###############################################################
#  Generated by:      Cadence Innovus 20.13-s083_1
#  OS:                Linux x86_64(Host ID iron-502-28)
#  Generated on:      Tue May 24 09:04:44 2022
#  Design:            top
#  Command:           write_lef_abstract -specifyTopLayer 6 -PGPinLayers {5 6} -noCutObs -stripePin results/top.lef
###############################################################

VERSION 5.8 ;

BUSBITCHARS "[]" ;
DIVIDERCHAR "/" ;

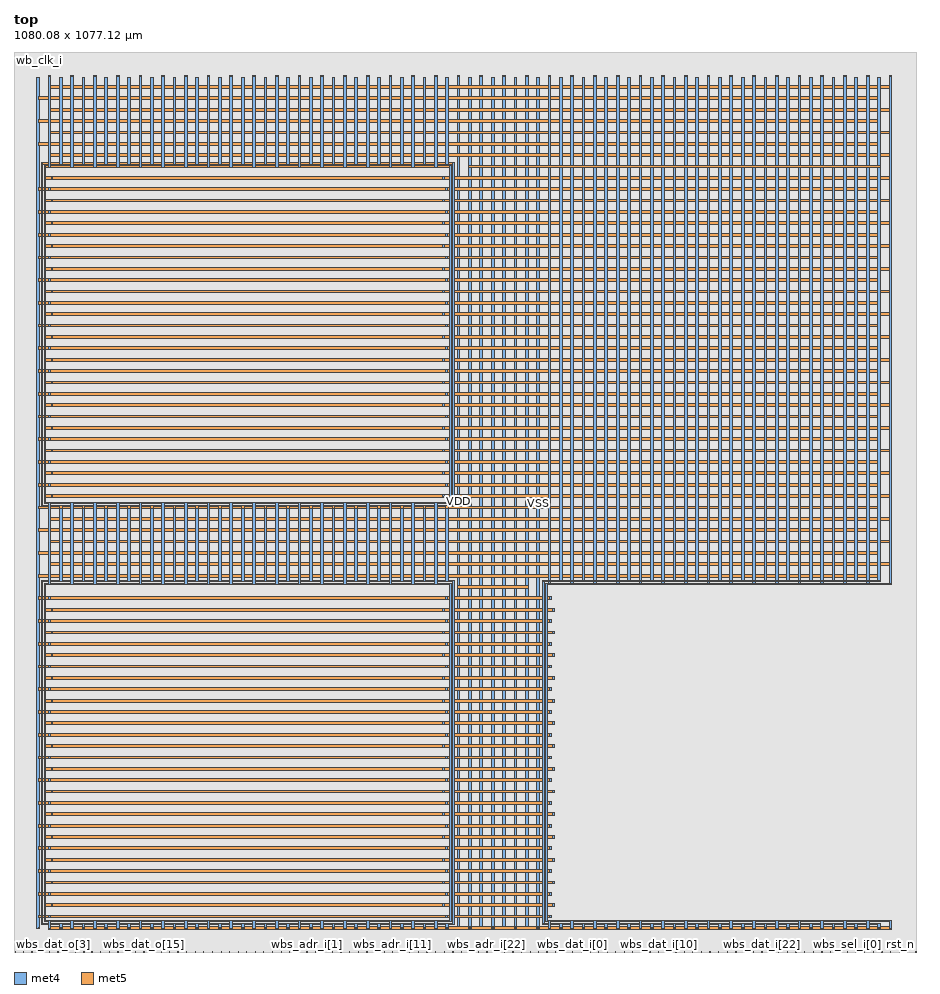
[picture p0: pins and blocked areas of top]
MACRO top
  CLASS BLOCK ;
  SIZE 1080.080000 BY 1077.120000 ;
  FOREIGN top 0.000000 0.000000 ;
  ORIGIN 0 0 ;
  SYMMETRY X Y R90 ;
  PIN clk
    DIRECTION INPUT ;
    USE SIGNAL ;
    ANTENNAPARTIALMETALAREA 0.4614 LAYER met4  ;
    ANTENNAPARTIALMETALSIDEAREA 2.456 LAYER met4  ;
    ANTENNAMODEL OXIDE1 ;
    ANTENNAGATEAREA 1.152 LAYER met4  ;
    ANTENNAMAXAREACAR 9.15953 LAYER met4  ;
    ANTENNAMAXSIDEAREACAR 47.4913 LAYER met4  ;
    ANTENNAMAXCUTCAR 0.114063 LAYER via4  ;
    PORT
      LAYER met4 ;
        RECT 0.000000 0.520000 0.800000 0.820000 ;
    END
  END clk
  PIN rst_n
    DIRECTION INPUT ;
    USE SIGNAL ;
    ANTENNAPARTIALMETALAREA 18.2562 LAYER met4  ;
    ANTENNAPARTIALMETALSIDEAREA 97.832 LAYER met4  ;
    ANTENNAMODEL OXIDE1 ;
    ANTENNAGATEAREA 4.6015 LAYER met4  ;
    ANTENNAMAXAREACAR 77.0933 LAYER met4  ;
    ANTENNAMAXSIDEAREACAR 375.091 LAYER met4  ;
    ANTENNAMAXCUTCAR 0.69315 LAYER via4  ;
    PORT
      LAYER met4 ;
        RECT 1079.240000 0.000000 1079.540000 0.800000 ;
    END
  END rst_n
  PIN wb_clk_i
    DIRECTION INPUT ;
    USE SIGNAL ;
    ANTENNAPARTIALMETALAREA 22.4322 LAYER met4  ;
    ANTENNAPARTIALMETALSIDEAREA 120.104 LAYER met4  ;
    ANTENNAMODEL OXIDE1 ;
    ANTENNAGATEAREA 0.477 LAYER met4  ;
    ANTENNAMAXAREACAR 77.5688 LAYER met4  ;
    ANTENNAMAXSIDEAREACAR 404.384 LAYER met4  ;
    ANTENNAMAXCUTCAR 1.05178 LAYER via4  ;
    PORT
      LAYER met4 ;
        RECT 0.000000 1076.560000 0.800000 1076.860000 ;
    END
  END wb_clk_i
  PIN wb_rst_i
    DIRECTION INPUT ;
    USE SIGNAL ;
    ANTENNAPARTIALMETALAREA 4.4604 LAYER met4  ;
    ANTENNAPARTIALMETALSIDEAREA 23.784 LAYER met4  ;
    ANTENNAMODEL OXIDE1 ;
    ANTENNAGATEAREA 8.3265 LAYER met4  ;
    ANTENNAMAXAREACAR 21.9302 LAYER met4  ;
    ANTENNAMAXSIDEAREACAR 109.513 LAYER met4  ;
    ANTENNAMAXCUTCAR 0.317271 LAYER via4  ;
    PORT
      LAYER met4 ;
        RECT 1069.580000 0.000000 1069.880000 0.800000 ;
    END
  END wb_rst_i
  PIN wbs_stb_i
    DIRECTION INPUT ;
    USE SIGNAL ;
    ANTENNAPARTIALMETALAREA 8.8044 LAYER met4  ;
    ANTENNAPARTIALMETALSIDEAREA 46.952 LAYER met4  ;
    ANTENNAMODEL OXIDE1 ;
    ANTENNAGATEAREA 0.2475 LAYER met4  ;
    ANTENNAMAXAREACAR 52.3097 LAYER met4  ;
    ANTENNAMAXSIDEAREACAR 278.307 LAYER met4  ;
    ANTENNAMAXCUTCAR 0.530909 LAYER via4  ;
    PORT
      LAYER met4 ;
        RECT 1059.230000 0.000000 1059.530000 0.800000 ;
    END
  END wbs_stb_i
  PIN wbs_cyc_i
    DIRECTION INPUT ;
    USE SIGNAL ;
    ANTENNAPARTIALMETALAREA 7.7064 LAYER met4  ;
    ANTENNAPARTIALMETALSIDEAREA 41.096 LAYER met4  ;
    ANTENNAMODEL OXIDE1 ;
    ANTENNAGATEAREA 0.2475 LAYER met4  ;
    ANTENNAMAXAREACAR 35.9594 LAYER met4  ;
    ANTENNAMAXSIDEAREACAR 190.17 LAYER met4  ;
    ANTENNAMAXCUTCAR 0.530909 LAYER via4  ;
    PORT
      LAYER met4 ;
        RECT 1048.880000 0.000000 1049.180000 0.800000 ;
    END
  END wbs_cyc_i
  PIN wbs_we_i
    DIRECTION INPUT ;
    USE SIGNAL ;
    ANTENNAPARTIALMETALAREA 0.855 LAYER met4  ;
    ANTENNAPARTIALMETALSIDEAREA 5.496 LAYER met4  ;
    ANTENNAMODEL OXIDE1 ;
    ANTENNAGATEAREA 0.126 LAYER met4  ;
    ANTENNAMAXAREACAR 59.1905 LAYER met4  ;
    ANTENNAMAXSIDEAREACAR 309.278 LAYER met4  ;
    ANTENNAMAXCUTCAR 1.04286 LAYER via4  ;
    PORT
      LAYER met4 ;
        RECT 1038.530000 0.000000 1038.830000 0.800000 ;
    END
  END wbs_we_i
  PIN wbs_sel_i[3]
    DIRECTION INPUT ;
    USE SIGNAL ;
    PORT
      LAYER met4 ;
        RECT 1028.180000 0.000000 1028.480000 0.800000 ;
    END
  END wbs_sel_i[3]
  PIN wbs_sel_i[2]
    DIRECTION INPUT ;
    USE SIGNAL ;
    PORT
      LAYER met4 ;
        RECT 1017.830000 0.000000 1018.130000 0.800000 ;
    END
  END wbs_sel_i[2]
  PIN wbs_sel_i[1]
    DIRECTION INPUT ;
    USE SIGNAL ;
    PORT
      LAYER met4 ;
        RECT 1007.480000 0.000000 1007.780000 0.800000 ;
    END
  END wbs_sel_i[1]
  PIN wbs_sel_i[0]
    DIRECTION INPUT ;
    USE SIGNAL ;
    PORT
      LAYER met4 ;
        RECT 997.130000 0.000000 997.430000 0.800000 ;
    END
  END wbs_sel_i[0]
  PIN wbs_dat_i[31]
    DIRECTION INPUT ;
    USE SIGNAL ;
    ANTENNAPARTIALMETALAREA 8.6214 LAYER met4  ;
    ANTENNAPARTIALMETALSIDEAREA 45.976 LAYER met4  ;
    ANTENNAMODEL OXIDE1 ;
    ANTENNAGATEAREA 0.126 LAYER met4  ;
    ANTENNAMAXAREACAR 73.4778 LAYER met4  ;
    ANTENNAMAXSIDEAREACAR 389.548 LAYER met4  ;
    ANTENNAMAXCUTCAR 1.04286 LAYER via4  ;
    PORT
      LAYER met4 ;
        RECT 987.470000 0.000000 987.770000 0.800000 ;
    END
  END wbs_dat_i[31]
  PIN wbs_dat_i[30]
    DIRECTION INPUT ;
    USE SIGNAL ;
    ANTENNAPARTIALMETALAREA 8.4384 LAYER met4  ;
    ANTENNAPARTIALMETALSIDEAREA 45 LAYER met4  ;
    ANTENNAMODEL OXIDE1 ;
    ANTENNAGATEAREA 0.126 LAYER met4  ;
    ANTENNAMAXAREACAR 79.5143 LAYER met4  ;
    ANTENNAMAXSIDEAREACAR 420.96 LAYER met4  ;
    ANTENNAMAXCUTCAR 1.04286 LAYER via4  ;
    PORT
      LAYER met4 ;
        RECT 977.120000 0.000000 977.420000 0.800000 ;
    END
  END wbs_dat_i[30]
  PIN wbs_dat_i[29]
    DIRECTION INPUT ;
    USE SIGNAL ;
    ANTENNAPARTIALMETALAREA 8.0724 LAYER met4  ;
    ANTENNAPARTIALMETALSIDEAREA 43.048 LAYER met4  ;
    ANTENNAMODEL OXIDE1 ;
    ANTENNAGATEAREA 0.126 LAYER met4  ;
    ANTENNAMAXAREACAR 72.7563 LAYER met4  ;
    ANTENNAMAXSIDEAREACAR 383.31 LAYER met4  ;
    ANTENNAMAXCUTCAR 1.04286 LAYER via4  ;
    PORT
      LAYER met4 ;
        RECT 966.770000 0.000000 967.070000 0.800000 ;
    END
  END wbs_dat_i[29]
  PIN wbs_dat_i[28]
    DIRECTION INPUT ;
    USE SIGNAL ;
    ANTENNAPARTIALMETALAREA 4.698 LAYER met4  ;
    ANTENNAPARTIALMETALSIDEAREA 25.992 LAYER met4  ;
    ANTENNAMODEL OXIDE1 ;
    ANTENNAGATEAREA 0.126 LAYER met4  ;
    ANTENNAMAXAREACAR 71.4944 LAYER met4  ;
    ANTENNAMAXSIDEAREACAR 376.802 LAYER met4  ;
    ANTENNAMAXCUTCAR 1.04286 LAYER via4  ;
    PORT
      LAYER met4 ;
        RECT 956.420000 0.000000 956.720000 0.800000 ;
    END
  END wbs_dat_i[28]
  PIN wbs_dat_i[27]
    DIRECTION INPUT ;
    USE SIGNAL ;
    ANTENNAPARTIALMETALAREA 8.6214 LAYER met4  ;
    ANTENNAPARTIALMETALSIDEAREA 45.976 LAYER met4  ;
    ANTENNAMODEL OXIDE1 ;
    ANTENNAGATEAREA 0.126 LAYER met4  ;
    ANTENNAMAXAREACAR 80.0071 LAYER met4  ;
    ANTENNAMAXSIDEAREACAR 421.659 LAYER met4  ;
    ANTENNAMAXCUTCAR 1.04286 LAYER via4  ;
    PORT
      LAYER met4 ;
        RECT 946.070000 0.000000 946.370000 0.800000 ;
    END
  END wbs_dat_i[27]
  PIN wbs_dat_i[26]
    DIRECTION INPUT ;
    USE SIGNAL ;
    ANTENNAPARTIALMETALAREA 7.1574 LAYER met4  ;
    ANTENNAPARTIALMETALSIDEAREA 38.168 LAYER met4  ;
    ANTENNAMODEL OXIDE1 ;
    ANTENNAGATEAREA 0.126 LAYER met4  ;
    ANTENNAMAXAREACAR 68.0734 LAYER met4  ;
    ANTENNAMAXSIDEAREACAR 354.278 LAYER met4  ;
    ANTENNAMAXCUTCAR 1.04286 LAYER via4  ;
    PORT
      LAYER met4 ;
        RECT 935.720000 0.000000 936.020000 0.800000 ;
    END
  END wbs_dat_i[26]
  PIN wbs_dat_i[25]
    DIRECTION INPUT ;
    USE SIGNAL ;
    ANTENNAPARTIALMETALAREA 8.0724 LAYER met4  ;
    ANTENNAPARTIALMETALSIDEAREA 43.048 LAYER met4  ;
    ANTENNAMODEL OXIDE1 ;
    ANTENNAGATEAREA 0.126 LAYER met4  ;
    ANTENNAMAXAREACAR 75.9881 LAYER met4  ;
    ANTENNAMAXSIDEAREACAR 400.183 LAYER met4  ;
    ANTENNAMAXCUTCAR 1.04286 LAYER via4  ;
    PORT
      LAYER met4 ;
        RECT 925.370000 0.000000 925.670000 0.800000 ;
    END
  END wbs_dat_i[25]
  PIN wbs_dat_i[24]
    DIRECTION INPUT ;
    USE SIGNAL ;
    ANTENNAPARTIALMETALAREA 8.6214 LAYER met4  ;
    ANTENNAPARTIALMETALSIDEAREA 45.976 LAYER met4  ;
    ANTENNAMODEL OXIDE1 ;
    ANTENNAGATEAREA 0.126 LAYER met4  ;
    ANTENNAMAXAREACAR 75.0246 LAYER met4  ;
    ANTENNAMAXSIDEAREACAR 397.278 LAYER met4  ;
    ANTENNAMAXCUTCAR 1.04286 LAYER via4  ;
    PORT
      LAYER met4 ;
        RECT 915.020000 0.000000 915.320000 0.800000 ;
    END
  END wbs_dat_i[24]
  PIN wbs_dat_i[23]
    DIRECTION INPUT ;
    USE SIGNAL ;
    ANTENNAPARTIALMETALAREA 8.175 LAYER met4  ;
    ANTENNAPARTIALMETALSIDEAREA 44.536 LAYER met4  ;
    ANTENNAMODEL OXIDE1 ;
    ANTENNAGATEAREA 0.126 LAYER met4  ;
    ANTENNAMAXAREACAR 91.3944 LAYER met4  ;
    ANTENNAMAXSIDEAREACAR 488.968 LAYER met4  ;
    ANTENNAMAXCUTCAR 1.04286 LAYER via4  ;
    PORT
      LAYER met4 ;
        RECT 904.670000 0.000000 904.970000 0.800000 ;
    END
  END wbs_dat_i[23]
  PIN wbs_dat_i[22]
    DIRECTION INPUT ;
    USE SIGNAL ;
    ANTENNAPARTIALMETALAREA 7.3984 LAYER met4  ;
    ANTENNAPARTIALMETALSIDEAREA 35.328 LAYER met4  ;
    ANTENNAPARTIALCUTAREA 0.64 LAYER via4  ;
    ANTENNAPARTIALMETALAREA 5.872 LAYER met5  ;
    ANTENNAPARTIALMETALSIDEAREA 12.648 LAYER met5  ;
    ANTENNAMODEL OXIDE1 ;
    ANTENNAGATEAREA 0.126 LAYER met5  ;
    ANTENNAMAXAREACAR 98.6127 LAYER met5  ;
    ANTENNAMAXSIDEAREACAR 346.69 LAYER met5  ;
    PORT
      LAYER met4 ;
        RECT 895.010000 0.000000 895.310000 0.800000 ;
    END
  END wbs_dat_i[22]
  PIN wbs_dat_i[21]
    DIRECTION INPUT ;
    USE SIGNAL ;
    ANTENNAPARTIALMETALAREA 7.3404 LAYER met4  ;
    ANTENNAPARTIALMETALSIDEAREA 39.144 LAYER met4  ;
    ANTENNAMODEL OXIDE1 ;
    ANTENNAGATEAREA 0.126 LAYER met4  ;
    ANTENNAMAXAREACAR 68.6032 LAYER met4  ;
    ANTENNAMAXSIDEAREACAR 360.77 LAYER met4  ;
    ANTENNAMAXCUTCAR 1.04286 LAYER via4  ;
    PORT
      LAYER met4 ;
        RECT 884.660000 0.000000 884.960000 0.800000 ;
    END
  END wbs_dat_i[21]
  PIN wbs_dat_i[20]
    DIRECTION INPUT ;
    USE SIGNAL ;
    ANTENNAPARTIALMETALAREA 8.6214 LAYER met4  ;
    ANTENNAPARTIALMETALSIDEAREA 45.976 LAYER met4  ;
    ANTENNAMODEL OXIDE1 ;
    ANTENNAGATEAREA 0.126 LAYER met4  ;
    ANTENNAMAXAREACAR 78.4738 LAYER met4  ;
    ANTENNAMAXSIDEAREACAR 413.992 LAYER met4  ;
    ANTENNAMAXCUTCAR 1.04286 LAYER via4  ;
    PORT
      LAYER met4 ;
        RECT 874.310000 0.000000 874.610000 0.800000 ;
    END
  END wbs_dat_i[20]
  PIN wbs_dat_i[19]
    DIRECTION INPUT ;
    USE SIGNAL ;
    ANTENNAPARTIALMETALAREA 5.2024 LAYER met4  ;
    ANTENNAPARTIALMETALSIDEAREA 23.616 LAYER met4  ;
    ANTENNAPARTIALCUTAREA 0.64 LAYER via4  ;
    ANTENNAPARTIALMETALAREA 19.184 LAYER met5  ;
    ANTENNAPARTIALMETALSIDEAREA 40.296 LAYER met5  ;
    ANTENNAMODEL OXIDE1 ;
    ANTENNAGATEAREA 0.126 LAYER met5  ;
    ANTENNAMAXAREACAR 190.813 LAYER met5  ;
    ANTENNAMAXSIDEAREACAR 491.349 LAYER met5  ;
    PORT
      LAYER met4 ;
        RECT 863.960000 0.000000 864.260000 0.800000 ;
    END
  END wbs_dat_i[19]
  PIN wbs_dat_i[18]
    DIRECTION INPUT ;
    USE SIGNAL ;
    ANTENNAPARTIALMETALAREA 8.6214 LAYER met4  ;
    ANTENNAPARTIALMETALSIDEAREA 45.976 LAYER met4  ;
    ANTENNAMODEL OXIDE1 ;
    ANTENNAGATEAREA 0.126 LAYER met4  ;
    ANTENNAMAXAREACAR 75.9183 LAYER met4  ;
    ANTENNAMAXSIDEAREACAR 401.214 LAYER met4  ;
    ANTENNAMAXCUTCAR 1.04286 LAYER via4  ;
    PORT
      LAYER met4 ;
        RECT 853.610000 0.000000 853.910000 0.800000 ;
    END
  END wbs_dat_i[18]
  PIN wbs_dat_i[17]
    DIRECTION INPUT ;
    USE SIGNAL ;
    ANTENNAPARTIALMETALAREA 0.2034 LAYER met4  ;
    ANTENNAPARTIALMETALSIDEAREA 1.08 LAYER met4  ;
    ANTENNAMODEL OXIDE1 ;
    ANTENNAGATEAREA 0.126 LAYER met4  ;
    ANTENNAMAXAREACAR 44.25 LAYER met4  ;
    ANTENNAMAXSIDEAREACAR 220.857 LAYER met4  ;
    ANTENNAMAXCUTCAR 1.04286 LAYER via4  ;
    PORT
      LAYER met4 ;
        RECT 843.260000 0.000000 843.560000 0.800000 ;
    END
  END wbs_dat_i[17]
  PIN wbs_dat_i[16]
    DIRECTION INPUT ;
    USE SIGNAL ;
    ANTENNAPARTIALMETALAREA 8.0724 LAYER met4  ;
    ANTENNAPARTIALMETALSIDEAREA 43.048 LAYER met4  ;
    ANTENNAMODEL OXIDE1 ;
    ANTENNAGATEAREA 0.126 LAYER met4  ;
    ANTENNAMAXAREACAR 78.3246 LAYER met4  ;
    ANTENNAMAXSIDEAREACAR 413.325 LAYER met4  ;
    ANTENNAMAXCUTCAR 1.04286 LAYER via4  ;
    PORT
      LAYER met4 ;
        RECT 832.910000 0.000000 833.210000 0.800000 ;
    END
  END wbs_dat_i[16]
  PIN wbs_dat_i[15]
    DIRECTION INPUT ;
    USE SIGNAL ;
    ANTENNAPARTIALMETALAREA 8.9874 LAYER met4  ;
    ANTENNAPARTIALMETALSIDEAREA 47.928 LAYER met4  ;
    ANTENNAMODEL OXIDE1 ;
    ANTENNAGATEAREA 0.126 LAYER met4  ;
    ANTENNAMAXAREACAR 83.4286 LAYER met4  ;
    ANTENNAMAXSIDEAREACAR 440.159 LAYER met4  ;
    ANTENNAMAXCUTCAR 1.04286 LAYER via4  ;
    PORT
      LAYER met4 ;
        RECT 822.560000 0.000000 822.860000 0.800000 ;
    END
  END wbs_dat_i[15]
  PIN wbs_dat_i[14]
    DIRECTION INPUT ;
    USE SIGNAL ;
    ANTENNAPARTIALMETALAREA 8.6214 LAYER met4  ;
    ANTENNAPARTIALMETALSIDEAREA 45.976 LAYER met4  ;
    ANTENNAMODEL OXIDE1 ;
    ANTENNAGATEAREA 0.126 LAYER met4  ;
    ANTENNAMAXAREACAR 79.7341 LAYER met4  ;
    ANTENNAMAXSIDEAREACAR 421.373 LAYER met4  ;
    ANTENNAMAXCUTCAR 1.04286 LAYER via4  ;
    PORT
      LAYER met4 ;
        RECT 812.210000 0.000000 812.510000 0.800000 ;
    END
  END wbs_dat_i[14]
  PIN wbs_dat_i[13]
    DIRECTION INPUT ;
    USE SIGNAL ;
    ANTENNAPARTIALMETALAREA 8.0724 LAYER met4  ;
    ANTENNAPARTIALMETALSIDEAREA 43.048 LAYER met4  ;
    ANTENNAMODEL OXIDE1 ;
    ANTENNAGATEAREA 0.126 LAYER met4  ;
    ANTENNAMAXAREACAR 76.3341 LAYER met4  ;
    ANTENNAMAXSIDEAREACAR 401.198 LAYER met4  ;
    ANTENNAMAXCUTCAR 1.04286 LAYER via4  ;
    PORT
      LAYER met4 ;
        RECT 802.550000 0.000000 802.850000 0.800000 ;
    END
  END wbs_dat_i[13]
  PIN wbs_dat_i[12]
    DIRECTION INPUT ;
    USE SIGNAL ;
    ANTENNAPARTIALMETALAREA 7.3404 LAYER met4  ;
    ANTENNAPARTIALMETALSIDEAREA 39.144 LAYER met4  ;
    ANTENNAMODEL OXIDE1 ;
    ANTENNAGATEAREA 0.126 LAYER met4  ;
    ANTENNAMAXAREACAR 68.7183 LAYER met4  ;
    ANTENNAMAXSIDEAREACAR 361.881 LAYER met4  ;
    ANTENNAMAXCUTCAR 1.04286 LAYER via4  ;
    PORT
      LAYER met4 ;
        RECT 792.200000 0.000000 792.500000 0.800000 ;
    END
  END wbs_dat_i[12]
  PIN wbs_dat_i[11]
    DIRECTION INPUT ;
    USE SIGNAL ;
    ANTENNAPARTIALMETALAREA 8.0724 LAYER met4  ;
    ANTENNAPARTIALMETALSIDEAREA 43.048 LAYER met4  ;
    ANTENNAMODEL OXIDE1 ;
    ANTENNAGATEAREA 0.126 LAYER met4  ;
    ANTENNAMAXAREACAR 72.8484 LAYER met4  ;
    ANTENNAMAXSIDEAREACAR 384.119 LAYER met4  ;
    ANTENNAMAXCUTCAR 1.04286 LAYER via4  ;
    PORT
      LAYER met4 ;
        RECT 781.850000 0.000000 782.150000 0.800000 ;
    END
  END wbs_dat_i[11]
  PIN wbs_dat_i[10]
    DIRECTION INPUT ;
    USE SIGNAL ;
    ANTENNAPARTIALMETALAREA 8.4384 LAYER met4  ;
    ANTENNAPARTIALMETALSIDEAREA 45 LAYER met4  ;
    ANTENNAMODEL OXIDE1 ;
    ANTENNAGATEAREA 0.126 LAYER met4  ;
    ANTENNAMAXAREACAR 76.6246 LAYER met4  ;
    ANTENNAMAXSIDEAREACAR 404.881 LAYER met4  ;
    ANTENNAMAXCUTCAR 1.04286 LAYER via4  ;
    PORT
      LAYER met4 ;
        RECT 771.500000 0.000000 771.800000 0.800000 ;
    END
  END wbs_dat_i[10]
  PIN wbs_dat_i[9]
    DIRECTION INPUT ;
    USE SIGNAL ;
    ANTENNAPARTIALMETALAREA 1.587 LAYER met4  ;
    ANTENNAPARTIALMETALSIDEAREA 9.4 LAYER met4  ;
    ANTENNAMODEL OXIDE1 ;
    ANTENNAGATEAREA 0.126 LAYER met4  ;
    ANTENNAMAXAREACAR 57.4849 LAYER met4  ;
    ANTENNAMAXSIDEAREACAR 299.984 LAYER met4  ;
    ANTENNAMAXCUTCAR 1.04286 LAYER via4  ;
    PORT
      LAYER met4 ;
        RECT 761.150000 0.000000 761.450000 0.800000 ;
    END
  END wbs_dat_i[9]
  PIN wbs_dat_i[8]
    DIRECTION INPUT ;
    USE SIGNAL ;
    ANTENNAPARTIALMETALAREA 2.709 LAYER met4  ;
    ANTENNAPARTIALMETALSIDEAREA 15.384 LAYER met4  ;
    ANTENNAMODEL OXIDE1 ;
    ANTENNAGATEAREA 0.126 LAYER met4  ;
    ANTENNAMAXAREACAR 66.1095 LAYER met4  ;
    ANTENNAMAXSIDEAREACAR 348.802 LAYER met4  ;
    ANTENNAMAXCUTCAR 1.04286 LAYER via4  ;
    PORT
      LAYER met4 ;
        RECT 750.800000 0.000000 751.100000 0.800000 ;
    END
  END wbs_dat_i[8]
  PIN wbs_dat_i[7]
    DIRECTION INPUT ;
    USE SIGNAL ;
    ANTENNAPARTIALMETALAREA 0.855 LAYER met4  ;
    ANTENNAPARTIALMETALSIDEAREA 5.496 LAYER met4  ;
    ANTENNAMODEL OXIDE1 ;
    ANTENNAGATEAREA 0.126 LAYER met4  ;
    ANTENNAMAXAREACAR 61.823 LAYER met4  ;
    ANTENNAMAXSIDEAREACAR 318.643 LAYER met4  ;
    ANTENNAMAXCUTCAR 1.04286 LAYER via4  ;
    PORT
      LAYER met4 ;
        RECT 740.450000 0.000000 740.750000 0.800000 ;
    END
  END wbs_dat_i[7]
  PIN wbs_dat_i[6]
    DIRECTION INPUT ;
    USE SIGNAL ;
    ANTENNAPARTIALMETALAREA 3.783 LAYER met4  ;
    ANTENNAPARTIALMETALSIDEAREA 21.112 LAYER met4  ;
    ANTENNAMODEL OXIDE1 ;
    ANTENNAGATEAREA 0.126 LAYER met4  ;
    ANTENNAMAXAREACAR 63.4754 LAYER met4  ;
    ANTENNAMAXSIDEAREACAR 333.556 LAYER met4  ;
    ANTENNAMAXCUTCAR 1.04286 LAYER via4  ;
    PORT
      LAYER met4 ;
        RECT 730.100000 0.000000 730.400000 0.800000 ;
    END
  END wbs_dat_i[6]
  PIN wbs_dat_i[5]
    DIRECTION INPUT ;
    USE SIGNAL ;
    ANTENNAPARTIALMETALAREA 1.953 LAYER met4  ;
    ANTENNAPARTIALMETALSIDEAREA 11.352 LAYER met4  ;
    ANTENNAMODEL OXIDE1 ;
    ANTENNAGATEAREA 0.126 LAYER met4  ;
    ANTENNAMAXAREACAR 63.5246 LAYER met4  ;
    ANTENNAMAXSIDEAREACAR 333.159 LAYER met4  ;
    ANTENNAMAXCUTCAR 1.04286 LAYER via4  ;
    PORT
      LAYER met4 ;
        RECT 719.750000 0.000000 720.050000 0.800000 ;
    END
  END wbs_dat_i[5]
  PIN wbs_dat_i[4]
    DIRECTION INPUT ;
    USE SIGNAL ;
    ANTENNAPARTIALMETALAREA 1.221 LAYER met4  ;
    ANTENNAPARTIALMETALSIDEAREA 7.448 LAYER met4  ;
    ANTENNAMODEL OXIDE1 ;
    ANTENNAGATEAREA 0.126 LAYER met4  ;
    ANTENNAMAXAREACAR 73.3357 LAYER met4  ;
    ANTENNAMAXSIDEAREACAR 380.825 LAYER met4  ;
    ANTENNAMAXCUTCAR 1.04286 LAYER via4  ;
    PORT
      LAYER met4 ;
        RECT 710.090000 0.000000 710.390000 0.800000 ;
    END
  END wbs_dat_i[4]
  PIN wbs_dat_i[3]
    DIRECTION INPUT ;
    USE SIGNAL ;
    ANTENNAPARTIALMETALAREA 4.332 LAYER met4  ;
    ANTENNAPARTIALMETALSIDEAREA 24.04 LAYER met4  ;
    ANTENNAMODEL OXIDE1 ;
    ANTENNAGATEAREA 0.126 LAYER met4  ;
    ANTENNAMAXAREACAR 64.546 LAYER met4  ;
    ANTENNAMAXSIDEAREACAR 342.722 LAYER met4  ;
    ANTENNAMAXCUTCAR 1.04286 LAYER via4  ;
    PORT
      LAYER met4 ;
        RECT 699.740000 0.000000 700.040000 0.800000 ;
    END
  END wbs_dat_i[3]
  PIN wbs_dat_i[2]
    DIRECTION INPUT ;
    USE SIGNAL ;
    ANTENNAPARTIALMETALAREA 3.234 LAYER met4  ;
    ANTENNAPARTIALMETALSIDEAREA 18.184 LAYER met4  ;
    ANTENNAMODEL OXIDE1 ;
    ANTENNAGATEAREA 0.126 LAYER met4  ;
    ANTENNAMAXAREACAR 63.5972 LAYER met4  ;
    ANTENNAMAXSIDEAREACAR 322.936 LAYER met4  ;
    ANTENNAMAXCUTCAR 1.04286 LAYER via4  ;
    PORT
      LAYER met4 ;
        RECT 689.390000 0.000000 689.690000 0.800000 ;
    END
  END wbs_dat_i[2]
  PIN wbs_dat_i[1]
    DIRECTION INPUT ;
    USE SIGNAL ;
    ANTENNAPARTIALMETALAREA 2.319 LAYER met4  ;
    ANTENNAPARTIALMETALSIDEAREA 13.304 LAYER met4  ;
    ANTENNAMODEL OXIDE1 ;
    ANTENNAGATEAREA 0.126 LAYER met4  ;
    ANTENNAMAXAREACAR 78.0643 LAYER met4  ;
    ANTENNAMAXSIDEAREACAR 406.071 LAYER met4  ;
    ANTENNAMAXCUTCAR 1.04286 LAYER via4  ;
    PORT
      LAYER met4 ;
        RECT 679.040000 0.000000 679.340000 0.800000 ;
    END
  END wbs_dat_i[1]
  PIN wbs_dat_i[0]
    DIRECTION INPUT ;
    USE SIGNAL ;
    ANTENNAPARTIALMETALAREA 2.685 LAYER met4  ;
    ANTENNAPARTIALMETALSIDEAREA 15.256 LAYER met4  ;
    ANTENNAMODEL OXIDE1 ;
    ANTENNAGATEAREA 0.126 LAYER met4  ;
    ANTENNAMAXAREACAR 106.781 LAYER met4  ;
    ANTENNAMAXSIDEAREACAR 543.976 LAYER met4  ;
    ANTENNAMAXCUTCAR 1.04286 LAYER via4  ;
    PORT
      LAYER met4 ;
        RECT 668.690000 0.000000 668.990000 0.800000 ;
    END
  END wbs_dat_i[0]
  PIN wbs_adr_i[31]
    DIRECTION INPUT ;
    USE SIGNAL ;
    ANTENNAPARTIALMETALAREA 1.587 LAYER met4  ;
    ANTENNAPARTIALMETALSIDEAREA 9.4 LAYER met4  ;
    ANTENNAMODEL OXIDE1 ;
    ANTENNAGATEAREA 0.126 LAYER met4  ;
    ANTENNAMAXAREACAR 70.9282 LAYER met4  ;
    ANTENNAMAXSIDEAREACAR 358.603 LAYER met4  ;
    ANTENNAMAXCUTCAR 1.04286 LAYER via4  ;
    PORT
      LAYER met4 ;
        RECT 658.340000 0.000000 658.640000 0.800000 ;
    END
  END wbs_adr_i[31]
  PIN wbs_adr_i[30]
    DIRECTION INPUT ;
    USE SIGNAL ;
    ANTENNAPARTIALMETALAREA 4.1424 LAYER met4  ;
    ANTENNAPARTIALMETALSIDEAREA 22.088 LAYER met4  ;
    ANTENNAMODEL OXIDE1 ;
    ANTENNAGATEAREA 0.126 LAYER met4  ;
    ANTENNAMAXAREACAR 129.885 LAYER met4  ;
    ANTENNAMAXSIDEAREACAR 668.77 LAYER met4  ;
    ANTENNAMAXCUTCAR 1.04286 LAYER via4  ;
    PORT
      LAYER met4 ;
        RECT 647.990000 0.000000 648.290000 0.800000 ;
    END
  END wbs_adr_i[30]
  PIN wbs_adr_i[29]
    DIRECTION INPUT ;
    USE SIGNAL ;
    ANTENNAPARTIALMETALAREA 9.2184 LAYER met4  ;
    ANTENNAPARTIALMETALSIDEAREA 49.16 LAYER met4  ;
    ANTENNAMODEL OXIDE1 ;
    ANTENNAGATEAREA 0.2475 LAYER met4  ;
    ANTENNAMAXAREACAR 90.6792 LAYER met4  ;
    ANTENNAMAXSIDEAREACAR 478.424 LAYER met4  ;
    ANTENNAMAXCUTCAR 0.530909 LAYER via4  ;
    PORT
      LAYER met4 ;
        RECT 637.640000 0.000000 637.940000 0.800000 ;
    END
  END wbs_adr_i[29]
  PIN wbs_adr_i[28]
    DIRECTION INPUT ;
    USE SIGNAL ;
    ANTENNAPARTIALMETALAREA 4.8264 LAYER met4  ;
    ANTENNAPARTIALMETALSIDEAREA 25.736 LAYER met4  ;
    ANTENNAMODEL OXIDE1 ;
    ANTENNAGATEAREA 0.2475 LAYER met4  ;
    ANTENNAMAXAREACAR 80.8723 LAYER met4  ;
    ANTENNAMAXSIDEAREACAR 423.79 LAYER met4  ;
    ANTENNAMAXCUTCAR 0.530909 LAYER via4  ;
    PORT
      LAYER met4 ;
        RECT 627.980000 0.000000 628.280000 0.800000 ;
    END
  END wbs_adr_i[28]
  PIN wbs_adr_i[27]
    DIRECTION INPUT ;
    USE SIGNAL ;
    ANTENNAPARTIALMETALAREA 6.0594 LAYER met4  ;
    ANTENNAPARTIALMETALSIDEAREA 32.312 LAYER met4  ;
    ANTENNAMODEL OXIDE1 ;
    ANTENNAGATEAREA 0.126 LAYER met4  ;
    ANTENNAMAXAREACAR 64.3516 LAYER met4  ;
    ANTENNAMAXSIDEAREACAR 334.087 LAYER met4  ;
    ANTENNAMAXCUTCAR 1.04286 LAYER via4  ;
    PORT
      LAYER met4 ;
        RECT 617.630000 0.000000 617.930000 0.800000 ;
    END
  END wbs_adr_i[27]
  PIN wbs_adr_i[26]
    DIRECTION INPUT ;
    USE SIGNAL ;
    ANTENNAPARTIALMETALAREA 8.4384 LAYER met4  ;
    ANTENNAPARTIALMETALSIDEAREA 45 LAYER met4  ;
    ANTENNAMODEL OXIDE1 ;
    ANTENNAGATEAREA 0.126 LAYER met4  ;
    ANTENNAMAXAREACAR 92.8361 LAYER met4  ;
    ANTENNAMAXSIDEAREACAR 490.96 LAYER met4  ;
    ANTENNAMAXCUTCAR 1.04286 LAYER via4  ;
    PORT
      LAYER met4 ;
        RECT 607.280000 0.000000 607.580000 0.800000 ;
    END
  END wbs_adr_i[26]
  PIN wbs_adr_i[25]
    DIRECTION INPUT ;
    USE SIGNAL ;
    ANTENNAPARTIALMETALAREA 8.2794 LAYER met4  ;
    ANTENNAPARTIALMETALSIDEAREA 44.152 LAYER met4  ;
    ANTENNAMODEL OXIDE1 ;
    ANTENNAGATEAREA 0.126 LAYER met4  ;
    ANTENNAMAXAREACAR 117.358 LAYER met4  ;
    ANTENNAMAXSIDEAREACAR 619.762 LAYER met4  ;
    ANTENNAMAXCUTCAR 1.04286 LAYER via4  ;
    PORT
      LAYER met4 ;
        RECT 596.930000 0.000000 597.230000 0.800000 ;
    END
  END wbs_adr_i[25]
  PIN wbs_adr_i[24]
    DIRECTION INPUT ;
    USE SIGNAL ;
    ANTENNAPARTIALMETALAREA 4.0464 LAYER met4  ;
    ANTENNAPARTIALMETALSIDEAREA 21.576 LAYER met4  ;
    ANTENNAMODEL OXIDE1 ;
    ANTENNAGATEAREA 0.126 LAYER met4  ;
    ANTENNAMAXAREACAR 76.1492 LAYER met4  ;
    ANTENNAMAXSIDEAREACAR 385.222 LAYER met4  ;
    ANTENNAMAXCUTCAR 1.04286 LAYER via4  ;
    PORT
      LAYER met4 ;
        RECT 586.580000 0.000000 586.880000 0.800000 ;
    END
  END wbs_adr_i[24]
  PIN wbs_adr_i[23]
    DIRECTION INPUT ;
    USE SIGNAL ;
    ANTENNAPARTIALMETALAREA 8.8044 LAYER met4  ;
    ANTENNAPARTIALMETALSIDEAREA 46.952 LAYER met4  ;
    ANTENNAMODEL OXIDE1 ;
    ANTENNAGATEAREA 0.126 LAYER met4  ;
    ANTENNAMAXAREACAR 80.3837 LAYER met4  ;
    ANTENNAMAXSIDEAREACAR 412.722 LAYER met4  ;
    ANTENNAMAXCUTCAR 1.04286 LAYER via4  ;
    PORT
      LAYER met4 ;
        RECT 576.230000 0.000000 576.530000 0.800000 ;
    END
  END wbs_adr_i[23]
  PIN wbs_adr_i[22]
    DIRECTION INPUT ;
    USE SIGNAL ;
    ANTENNAPARTIALMETALAREA 8.9874 LAYER met4  ;
    ANTENNAPARTIALMETALSIDEAREA 47.928 LAYER met4  ;
    ANTENNAMODEL OXIDE1 ;
    ANTENNAGATEAREA 0.2475 LAYER met4  ;
    ANTENNAMAXAREACAR 41.1624 LAYER met4  ;
    ANTENNAMAXSIDEAREACAR 215.115 LAYER met4  ;
    ANTENNAMAXCUTCAR 0.530909 LAYER via4  ;
    PORT
      LAYER met4 ;
        RECT 565.880000 0.000000 566.180000 0.800000 ;
    END
  END wbs_adr_i[22]
  PIN wbs_adr_i[21]
    DIRECTION INPUT ;
    USE SIGNAL ;
    ANTENNAPARTIALMETALAREA 8.6214 LAYER met4  ;
    ANTENNAPARTIALMETALSIDEAREA 45.976 LAYER met4  ;
    ANTENNAMODEL OXIDE1 ;
    ANTENNAGATEAREA 0.126 LAYER met4  ;
    ANTENNAMAXAREACAR 113.275 LAYER met4  ;
    ANTENNAMAXSIDEAREACAR 593.508 LAYER met4  ;
    ANTENNAMAXCUTCAR 1.04286 LAYER via4  ;
    PORT
      LAYER met4 ;
        RECT 555.530000 0.000000 555.830000 0.800000 ;
    END
  END wbs_adr_i[21]
  PIN wbs_adr_i[20]
    DIRECTION INPUT ;
    USE SIGNAL ;
    ANTENNAPARTIALMETALAREA 7.7064 LAYER met4  ;
    ANTENNAPARTIALMETALSIDEAREA 41.096 LAYER met4  ;
    ANTENNAMODEL OXIDE1 ;
    ANTENNAGATEAREA 0.2475 LAYER met4  ;
    ANTENNAMAXAREACAR 54.0869 LAYER met4  ;
    ANTENNAMAXSIDEAREACAR 279.62 LAYER met4  ;
    ANTENNAMAXCUTCAR 0.530909 LAYER via4  ;
    PORT
      LAYER met4 ;
        RECT 545.180000 0.000000 545.480000 0.800000 ;
    END
  END wbs_adr_i[20]
  PIN wbs_adr_i[19]
    DIRECTION INPUT ;
    USE SIGNAL ;
    ANTENNAPARTIALMETALAREA 6.7914 LAYER met4  ;
    ANTENNAPARTIALMETALSIDEAREA 36.216 LAYER met4  ;
    ANTENNAMODEL OXIDE1 ;
    ANTENNAGATEAREA 0.2475 LAYER met4  ;
    ANTENNAMAXAREACAR 38.8085 LAYER met4  ;
    ANTENNAMAXSIDEAREACAR 203.632 LAYER met4  ;
    ANTENNAMAXCUTCAR 0.530909 LAYER via4  ;
    PORT
      LAYER met4 ;
        RECT 535.520000 0.000000 535.820000 0.800000 ;
    END
  END wbs_adr_i[19]
  PIN wbs_adr_i[18]
    DIRECTION INPUT ;
    USE SIGNAL ;
    ANTENNAPARTIALMETALAREA 6.7914 LAYER met4  ;
    ANTENNAPARTIALMETALSIDEAREA 36.216 LAYER met4  ;
    ANTENNAMODEL OXIDE1 ;
    ANTENNAGATEAREA 0.2475 LAYER met4  ;
    ANTENNAMAXAREACAR 41.087 LAYER met4  ;
    ANTENNAMAXSIDEAREACAR 211.248 LAYER met4  ;
    ANTENNAMAXCUTCAR 0.530909 LAYER via4  ;
    PORT
      LAYER met4 ;
        RECT 525.170000 0.000000 525.470000 0.800000 ;
    END
  END wbs_adr_i[18]
  PIN wbs_adr_i[17]
    DIRECTION INPUT ;
    USE SIGNAL ;
    ANTENNAPARTIALMETALAREA 6.7914 LAYER met4  ;
    ANTENNAPARTIALMETALSIDEAREA 36.216 LAYER met4  ;
    ANTENNAMODEL OXIDE1 ;
    ANTENNAGATEAREA 0.2475 LAYER met4  ;
    ANTENNAMAXAREACAR 43.3996 LAYER met4  ;
    ANTENNAMAXSIDEAREACAR 221.632 LAYER met4  ;
    ANTENNAMAXCUTCAR 0.530909 LAYER via4  ;
    PORT
      LAYER met4 ;
        RECT 514.820000 0.000000 515.120000 0.800000 ;
    END
  END wbs_adr_i[17]
  PIN wbs_adr_i[16]
    DIRECTION INPUT ;
    USE SIGNAL ;
    ANTENNAPARTIALMETALAREA 6.0594 LAYER met4  ;
    ANTENNAPARTIALMETALSIDEAREA 32.312 LAYER met4  ;
    ANTENNAMODEL OXIDE1 ;
    ANTENNAGATEAREA 0.2475 LAYER met4  ;
    ANTENNAMAXAREACAR 60.8457 LAYER met4  ;
    ANTENNAMAXSIDEAREACAR 318.525 LAYER met4  ;
    ANTENNAMAXCUTCAR 0.530909 LAYER via4  ;
    PORT
      LAYER met4 ;
        RECT 504.470000 0.000000 504.770000 0.800000 ;
    END
  END wbs_adr_i[16]
  PIN wbs_adr_i[15]
    DIRECTION INPUT ;
    USE SIGNAL ;
    ANTENNAPARTIALMETALAREA 6.7914 LAYER met4  ;
    ANTENNAPARTIALMETALSIDEAREA 36.216 LAYER met4  ;
    ANTENNAMODEL OXIDE1 ;
    ANTENNAGATEAREA 0.2475 LAYER met4  ;
    ANTENNAMAXAREACAR 42.4513 LAYER met4  ;
    ANTENNAMAXSIDEAREACAR 223.147 LAYER met4  ;
    ANTENNAMAXCUTCAR 0.530909 LAYER via4  ;
    PORT
      LAYER met4 ;
        RECT 494.120000 0.000000 494.420000 0.800000 ;
    END
  END wbs_adr_i[15]
  PIN wbs_adr_i[14]
    DIRECTION INPUT ;
    USE SIGNAL ;
    ANTENNAPARTIALMETALAREA 0.3864 LAYER met4  ;
    ANTENNAPARTIALMETALSIDEAREA 2.056 LAYER met4  ;
    ANTENNAMODEL OXIDE1 ;
    ANTENNAGATEAREA 0.2475 LAYER met4  ;
    ANTENNAMAXAREACAR 23.3447 LAYER met4  ;
    ANTENNAMAXSIDEAREACAR 112.424 LAYER met4  ;
    ANTENNAMAXCUTCAR 0.530909 LAYER via4  ;
    PORT
      LAYER met4 ;
        RECT 483.770000 0.000000 484.070000 0.800000 ;
    END
  END wbs_adr_i[14]
  PIN wbs_adr_i[13]
    DIRECTION INPUT ;
    USE SIGNAL ;
    ANTENNAPARTIALMETALAREA 5.3274 LAYER met4  ;
    ANTENNAPARTIALMETALSIDEAREA 28.408 LAYER met4  ;
    ANTENNAMODEL OXIDE1 ;
    ANTENNAGATEAREA 0.2475 LAYER met4  ;
    ANTENNAMAXAREACAR 44.5717 LAYER met4  ;
    ANTENNAMAXSIDEAREACAR 229.883 LAYER met4  ;
    ANTENNAMAXCUTCAR 0.530909 LAYER via4  ;
    PORT
      LAYER met4 ;
        RECT 473.420000 0.000000 473.720000 0.800000 ;
    END
  END wbs_adr_i[13]
  PIN wbs_adr_i[12]
    DIRECTION INPUT ;
    USE SIGNAL ;
    ANTENNAPARTIALMETALAREA 6.0594 LAYER met4  ;
    ANTENNAPARTIALMETALSIDEAREA 32.312 LAYER met4  ;
    ANTENNAMODEL OXIDE1 ;
    ANTENNAGATEAREA 0.2475 LAYER met4  ;
    ANTENNAMAXAREACAR 57.5002 LAYER met4  ;
    ANTENNAMAXSIDEAREACAR 300.683 LAYER met4  ;
    ANTENNAMAXCUTCAR 0.530909 LAYER via4  ;
    PORT
      LAYER met4 ;
        RECT 463.070000 0.000000 463.370000 0.800000 ;
    END
  END wbs_adr_i[12]
  PIN wbs_adr_i[11]
    DIRECTION INPUT ;
    USE SIGNAL ;
    ANTENNAPARTIALMETALAREA 4.7784 LAYER met4  ;
    ANTENNAPARTIALMETALSIDEAREA 25.48 LAYER met4  ;
    ANTENNAMODEL OXIDE1 ;
    ANTENNAGATEAREA 0.2475 LAYER met4  ;
    ANTENNAMAXAREACAR 91.1745 LAYER met4  ;
    ANTENNAMAXSIDEAREACAR 477.236 LAYER met4  ;
    ANTENNAMAXCUTCAR 0.530909 LAYER via4  ;
    PORT
      LAYER met4 ;
        RECT 452.720000 0.000000 453.020000 0.800000 ;
    END
  END wbs_adr_i[11]
  PIN wbs_adr_i[10]
    DIRECTION INPUT ;
    USE SIGNAL ;
    ANTENNAPARTIALMETALAREA 6.7914 LAYER met4  ;
    ANTENNAPARTIALMETALSIDEAREA 36.216 LAYER met4  ;
    ANTENNAMODEL OXIDE1 ;
    ANTENNAGATEAREA 0.495 LAYER met4  ;
    ANTENNAMAXAREACAR 26.1736 LAYER met4  ;
    ANTENNAMAXSIDEAREACAR 138.196 LAYER met4  ;
    ANTENNAMAXCUTCAR 0.265455 LAYER via4  ;
    PORT
      LAYER met4 ;
        RECT 443.060000 0.000000 443.360000 0.800000 ;
    END
  END wbs_adr_i[10]
  PIN wbs_adr_i[9]
    DIRECTION INPUT ;
    USE SIGNAL ;
    ANTENNAPARTIALMETALAREA 8.6214 LAYER met4  ;
    ANTENNAPARTIALMETALSIDEAREA 45.976 LAYER met4  ;
    ANTENNAMODEL OXIDE1 ;
    ANTENNAGATEAREA 0.7425 LAYER met4  ;
    ANTENNAMAXAREACAR 17.4768 LAYER met4  ;
    ANTENNAMAXSIDEAREACAR 89.7498 LAYER met4  ;
    ANTENNAMAXCUTCAR 0.315421 LAYER via4  ;
    PORT
      LAYER met4 ;
        RECT 432.710000 0.000000 433.010000 0.800000 ;
    END
  END wbs_adr_i[9]
  PIN wbs_adr_i[8]
    DIRECTION INPUT ;
    USE SIGNAL ;
    ANTENNAPARTIALMETALAREA 6.7914 LAYER met4  ;
    ANTENNAPARTIALMETALSIDEAREA 36.216 LAYER met4  ;
    ANTENNAMODEL OXIDE1 ;
    ANTENNAGATEAREA 0.7425 LAYER met4  ;
    ANTENNAMAXAREACAR 20.9349 LAYER met4  ;
    ANTENNAMAXSIDEAREACAR 104.734 LAYER met4  ;
    ANTENNAMAXCUTCAR 0.315421 LAYER via4  ;
    PORT
      LAYER met4 ;
        RECT 422.360000 0.000000 422.660000 0.800000 ;
    END
  END wbs_adr_i[8]
  PIN wbs_adr_i[7]
    DIRECTION INPUT ;
    USE SIGNAL ;
    ANTENNAPARTIALMETALAREA 9.3534 LAYER met4  ;
    ANTENNAPARTIALMETALSIDEAREA 49.88 LAYER met4  ;
    ANTENNAMODEL OXIDE1 ;
    ANTENNAGATEAREA 1.825 LAYER met4  ;
    ANTENNAMAXAREACAR 8.74914 LAYER met4  ;
    ANTENNAMAXSIDEAREACAR 43.4412 LAYER met4  ;
    ANTENNAMAXCUTCAR 0.147674 LAYER via4  ;
    PORT
      LAYER met4 ;
        RECT 412.010000 0.000000 412.310000 0.800000 ;
    END
  END wbs_adr_i[7]
  PIN wbs_adr_i[6]
    DIRECTION INPUT ;
    USE SIGNAL ;
    ANTENNAPARTIALMETALAREA 18.2562 LAYER met4  ;
    ANTENNAPARTIALMETALSIDEAREA 97.832 LAYER met4  ;
    ANTENNAMODEL OXIDE1 ;
    ANTENNAGATEAREA 1.5775 LAYER met4  ;
    ANTENNAMAXAREACAR 60.3892 LAYER met4  ;
    ANTENNAMAXSIDEAREACAR 313.595 LAYER met4  ;
    ANTENNAMAXCUTCAR 0.456964 LAYER via4  ;
    PORT
      LAYER met4 ;
        RECT 401.660000 0.000000 401.960000 0.800000 ;
    END
  END wbs_adr_i[6]
  PIN wbs_adr_i[5]
    DIRECTION INPUT ;
    USE SIGNAL ;
    ANTENNAPARTIALMETALAREA 4.2534 LAYER met4  ;
    ANTENNAPARTIALMETALSIDEAREA 22.68 LAYER met4  ;
    ANTENNAMODEL OXIDE1 ;
    ANTENNAGATEAREA 1.5775 LAYER met4  ;
    ANTENNAMAXAREACAR 79.849 LAYER met4  ;
    ANTENNAMAXSIDEAREACAR 406.622 LAYER met4  ;
    ANTENNAMAXCUTCAR 0.367778 LAYER via4  ;
    PORT
      LAYER met4 ;
        RECT 391.310000 0.000000 391.610000 0.800000 ;
    END
  END wbs_adr_i[5]
  PIN wbs_adr_i[4]
    DIRECTION INPUT ;
    USE SIGNAL ;
    ANTENNAPARTIALMETALAREA 1.3014 LAYER met4  ;
    ANTENNAPARTIALMETALSIDEAREA 6.936 LAYER met4  ;
    ANTENNAMODEL OXIDE1 ;
    ANTENNAGATEAREA 1.4075 LAYER met4  ;
    ANTENNAMAXAREACAR 24.4815 LAYER met4  ;
    ANTENNAMAXSIDEAREACAR 120.759 LAYER met4  ;
    ANTENNAMAXCUTCAR 0.264515 LAYER via4  ;
    PORT
      LAYER met4 ;
        RECT 380.960000 0.000000 381.260000 0.800000 ;
    END
  END wbs_adr_i[4]
  PIN wbs_adr_i[3]
    DIRECTION INPUT ;
    USE SIGNAL ;
    ANTENNAPARTIALMETALAREA 4.4124 LAYER met4  ;
    ANTENNAPARTIALMETALSIDEAREA 23.528 LAYER met4  ;
    ANTENNAMODEL OXIDE1 ;
    ANTENNAGATEAREA 1.5775 LAYER met4  ;
    ANTENNAMAXAREACAR 36.7685 LAYER met4  ;
    ANTENNAMAXSIDEAREACAR 181.953 LAYER met4  ;
    ANTENNAMAXCUTCAR 0.349299 LAYER via4  ;
    PORT
      LAYER met4 ;
        RECT 370.610000 0.000000 370.910000 0.800000 ;
    END
  END wbs_adr_i[3]
  PIN wbs_adr_i[2]
    DIRECTION INPUT ;
    USE SIGNAL ;
    ANTENNAPARTIALMETALAREA 6.0594 LAYER met4  ;
    ANTENNAPARTIALMETALSIDEAREA 32.312 LAYER met4  ;
    ANTENNAMODEL OXIDE1 ;
    ANTENNAGATEAREA 1.5775 LAYER met4  ;
    ANTENNAMAXAREACAR 18.4695 LAYER met4  ;
    ANTENNAMAXSIDEAREACAR 87.7004 LAYER met4  ;
    ANTENNAMAXCUTCAR 0.25839 LAYER via4  ;
    PORT
      LAYER met4 ;
        RECT 360.950000 0.000000 361.250000 0.800000 ;
    END
  END wbs_adr_i[2]
  PIN wbs_adr_i[1]
    DIRECTION INPUT ;
    USE SIGNAL ;
    ANTENNAPARTIALMETALAREA 3.6804 LAYER met4  ;
    ANTENNAPARTIALMETALSIDEAREA 19.624 LAYER met4  ;
    ANTENNAMODEL OXIDE1 ;
    ANTENNAGATEAREA 1.5775 LAYER met4  ;
    ANTENNAMAXAREACAR 13.5082 LAYER met4  ;
    ANTENNAMAXSIDEAREACAR 64.4559 LAYER met4  ;
    ANTENNAMAXCUTCAR 0.25839 LAYER via4  ;
    PORT
      LAYER met4 ;
        RECT 350.600000 0.000000 350.900000 0.800000 ;
    END
  END wbs_adr_i[1]
  PIN wbs_adr_i[0]
    DIRECTION INPUT ;
    USE SIGNAL ;
    ANTENNAPARTIALMETALAREA 6.0594 LAYER met4  ;
    ANTENNAPARTIALMETALSIDEAREA 32.312 LAYER met4  ;
    ANTENNAMODEL OXIDE1 ;
    ANTENNAGATEAREA 0.665 LAYER met4  ;
    ANTENNAMAXAREACAR 12.2292 LAYER met4  ;
    ANTENNAMAXSIDEAREACAR 62.7519 LAYER met4  ;
    ANTENNAMAXCUTCAR 0.197594 LAYER via4  ;
    PORT
      LAYER met4 ;
        RECT 340.250000 0.000000 340.550000 0.800000 ;
    END
  END wbs_adr_i[0]
  PIN wbs_ack_o
    DIRECTION OUTPUT ;
    USE SIGNAL ;
    ANTENNADIFFAREA 0.429 LAYER met4  ;
    ANTENNAPARTIALMETALAREA 0.2034 LAYER met4  ;
    ANTENNAPARTIALMETALSIDEAREA 1.08 LAYER met4  ;
    PORT
      LAYER met4 ;
        RECT 329.900000 0.000000 330.200000 0.800000 ;
    END
  END wbs_ack_o
  PIN wbs_dat_o[31]
    DIRECTION OUTPUT ;
    USE SIGNAL ;
    ANTENNADIFFAREA 0.43675 LAYER met4  ;
    ANTENNAPARTIALMETALAREA 8.4384 LAYER met4  ;
    ANTENNAPARTIALMETALSIDEAREA 45 LAYER met4  ;
    PORT
      LAYER met4 ;
        RECT 319.550000 0.000000 319.850000 0.800000 ;
    END
  END wbs_dat_o[31]
  PIN wbs_dat_o[30]
    DIRECTION OUTPUT ;
    USE SIGNAL ;
    ANTENNADIFFAREA 0.43675 LAYER met4  ;
    ANTENNAPARTIALMETALAREA 6.0594 LAYER met4  ;
    ANTENNAPARTIALMETALSIDEAREA 32.312 LAYER met4  ;
    PORT
      LAYER met4 ;
        RECT 309.200000 0.000000 309.500000 0.800000 ;
    END
  END wbs_dat_o[30]
  PIN wbs_dat_o[29]
    DIRECTION OUTPUT ;
    USE SIGNAL ;
    ANTENNADIFFAREA 0.43675 LAYER met4  ;
    ANTENNAPARTIALMETALAREA 6.0594 LAYER met4  ;
    ANTENNAPARTIALMETALSIDEAREA 32.312 LAYER met4  ;
    PORT
      LAYER met4 ;
        RECT 298.850000 0.000000 299.150000 0.800000 ;
    END
  END wbs_dat_o[29]
  PIN wbs_dat_o[28]
    DIRECTION OUTPUT ;
    USE SIGNAL ;
    ANTENNADIFFAREA 0.43675 LAYER met4  ;
    ANTENNAPARTIALMETALAREA 6.4254 LAYER met4  ;
    ANTENNAPARTIALMETALSIDEAREA 34.264 LAYER met4  ;
    PORT
      LAYER met4 ;
        RECT 288.500000 0.000000 288.800000 0.800000 ;
    END
  END wbs_dat_o[28]
  PIN wbs_dat_o[27]
    DIRECTION OUTPUT ;
    USE SIGNAL ;
    ANTENNADIFFAREA 0.43675 LAYER met4  ;
    ANTENNAPARTIALMETALAREA 8.4384 LAYER met4  ;
    ANTENNAPARTIALMETALSIDEAREA 45 LAYER met4  ;
    PORT
      LAYER met4 ;
        RECT 278.150000 0.000000 278.450000 0.800000 ;
    END
  END wbs_dat_o[27]
  PIN wbs_dat_o[26]
    DIRECTION OUTPUT ;
    USE SIGNAL ;
    ANTENNADIFFAREA 0.43675 LAYER met4  ;
    ANTENNAPARTIALMETALAREA 8.4384 LAYER met4  ;
    ANTENNAPARTIALMETALSIDEAREA 45 LAYER met4  ;
    PORT
      LAYER met4 ;
        RECT 268.490000 0.000000 268.790000 0.800000 ;
    END
  END wbs_dat_o[26]
  PIN wbs_dat_o[25]
    DIRECTION OUTPUT ;
    USE SIGNAL ;
    ANTENNADIFFAREA 0.43675 LAYER met4  ;
    ANTENNAPARTIALMETALAREA 7.7064 LAYER met4  ;
    ANTENNAPARTIALMETALSIDEAREA 41.096 LAYER met4  ;
    PORT
      LAYER met4 ;
        RECT 258.140000 0.000000 258.440000 0.800000 ;
    END
  END wbs_dat_o[25]
  PIN wbs_dat_o[24]
    DIRECTION OUTPUT ;
    USE SIGNAL ;
    ANTENNADIFFAREA 0.43675 LAYER met4  ;
    ANTENNAPARTIALMETALAREA 7.7064 LAYER met4  ;
    ANTENNAPARTIALMETALSIDEAREA 41.096 LAYER met4  ;
    PORT
      LAYER met4 ;
        RECT 247.790000 0.000000 248.090000 0.800000 ;
    END
  END wbs_dat_o[24]
  PIN wbs_dat_o[23]
    DIRECTION OUTPUT ;
    USE SIGNAL ;
    ANTENNADIFFAREA 0.43675 LAYER met4  ;
    ANTENNAPARTIALMETALAREA 7.1574 LAYER met4  ;
    ANTENNAPARTIALMETALSIDEAREA 38.168 LAYER met4  ;
    PORT
      LAYER met4 ;
        RECT 237.440000 0.000000 237.740000 0.800000 ;
    END
  END wbs_dat_o[23]
  PIN wbs_dat_o[22]
    DIRECTION OUTPUT ;
    USE SIGNAL ;
    ANTENNADIFFAREA 0.43675 LAYER met4  ;
    ANTENNAPARTIALMETALAREA 8.4384 LAYER met4  ;
    ANTENNAPARTIALMETALSIDEAREA 45 LAYER met4  ;
    PORT
      LAYER met4 ;
        RECT 227.090000 0.000000 227.390000 0.800000 ;
    END
  END wbs_dat_o[22]
  PIN wbs_dat_o[21]
    DIRECTION OUTPUT ;
    USE SIGNAL ;
    ANTENNADIFFAREA 0.43675 LAYER met4  ;
    ANTENNAPARTIALMETALAREA 8.4384 LAYER met4  ;
    ANTENNAPARTIALMETALSIDEAREA 45 LAYER met4  ;
    PORT
      LAYER met4 ;
        RECT 216.740000 0.000000 217.040000 0.800000 ;
    END
  END wbs_dat_o[21]
  PIN wbs_dat_o[20]
    DIRECTION OUTPUT ;
    USE SIGNAL ;
    ANTENNADIFFAREA 0.43675 LAYER met4  ;
    ANTENNAPARTIALMETALAREA 8.0724 LAYER met4  ;
    ANTENNAPARTIALMETALSIDEAREA 43.048 LAYER met4  ;
    PORT
      LAYER met4 ;
        RECT 206.390000 0.000000 206.690000 0.800000 ;
    END
  END wbs_dat_o[20]
  PIN wbs_dat_o[19]
    DIRECTION OUTPUT ;
    USE SIGNAL ;
    ANTENNADIFFAREA 0.43675 LAYER met4  ;
    ANTENNAPARTIALMETALAREA 7.5234 LAYER met4  ;
    ANTENNAPARTIALMETALSIDEAREA 40.12 LAYER met4  ;
    PORT
      LAYER met4 ;
        RECT 196.040000 0.000000 196.340000 0.800000 ;
    END
  END wbs_dat_o[19]
  PIN wbs_dat_o[18]
    DIRECTION OUTPUT ;
    USE SIGNAL ;
    ANTENNADIFFAREA 0.43675 LAYER met4  ;
    ANTENNAPARTIALMETALAREA 8.4384 LAYER met4  ;
    ANTENNAPARTIALMETALSIDEAREA 45 LAYER met4  ;
    PORT
      LAYER met4 ;
        RECT 185.690000 0.000000 185.990000 0.800000 ;
    END
  END wbs_dat_o[18]
  PIN wbs_dat_o[17]
    DIRECTION OUTPUT ;
    USE SIGNAL ;
    ANTENNADIFFAREA 0.43675 LAYER met4  ;
    ANTENNAPARTIALMETALAREA 8.4384 LAYER met4  ;
    ANTENNAPARTIALMETALSIDEAREA 45 LAYER met4  ;
    PORT
      LAYER met4 ;
        RECT 176.030000 0.000000 176.330000 0.800000 ;
    END
  END wbs_dat_o[17]
  PIN wbs_dat_o[16]
    DIRECTION OUTPUT ;
    USE SIGNAL ;
    ANTENNADIFFAREA 0.43675 LAYER met4  ;
    ANTENNAPARTIALMETALAREA 0.2034 LAYER met4  ;
    ANTENNAPARTIALMETALSIDEAREA 1.08 LAYER met4  ;
    PORT
      LAYER met4 ;
        RECT 165.680000 0.000000 165.980000 0.800000 ;
    END
  END wbs_dat_o[16]
  PIN wbs_dat_o[15]
    DIRECTION OUTPUT ;
    USE SIGNAL ;
    ANTENNADIFFAREA 0.43675 LAYER met4  ;
    ANTENNAPARTIALMETALAREA 8.4384 LAYER met4  ;
    ANTENNAPARTIALMETALSIDEAREA 45 LAYER met4  ;
    PORT
      LAYER met4 ;
        RECT 155.330000 0.000000 155.630000 0.800000 ;
    END
  END wbs_dat_o[15]
  PIN wbs_dat_o[14]
    DIRECTION OUTPUT ;
    USE SIGNAL ;
    ANTENNADIFFAREA 0.43675 LAYER met4  ;
    ANTENNAPARTIALMETALAREA 8.2554 LAYER met4  ;
    ANTENNAPARTIALMETALSIDEAREA 44.024 LAYER met4  ;
    PORT
      LAYER met4 ;
        RECT 144.980000 0.000000 145.280000 0.800000 ;
    END
  END wbs_dat_o[14]
  PIN wbs_dat_o[13]
    DIRECTION OUTPUT ;
    USE SIGNAL ;
    ANTENNADIFFAREA 0.43675 LAYER met4  ;
    ANTENNAPARTIALMETALAREA 8.4384 LAYER met4  ;
    ANTENNAPARTIALMETALSIDEAREA 45 LAYER met4  ;
    PORT
      LAYER met4 ;
        RECT 134.630000 0.000000 134.930000 0.800000 ;
    END
  END wbs_dat_o[13]
  PIN wbs_dat_o[12]
    DIRECTION OUTPUT ;
    USE SIGNAL ;
    ANTENNADIFFAREA 0.43675 LAYER met4  ;
    ANTENNAPARTIALMETALAREA 7.8894 LAYER met4  ;
    ANTENNAPARTIALMETALSIDEAREA 42.072 LAYER met4  ;
    PORT
      LAYER met4 ;
        RECT 124.280000 0.000000 124.580000 0.800000 ;
    END
  END wbs_dat_o[12]
  PIN wbs_dat_o[11]
    DIRECTION OUTPUT ;
    USE SIGNAL ;
    ANTENNADIFFAREA 0.43675 LAYER met4  ;
    ANTENNAPARTIALMETALAREA 8.4384 LAYER met4  ;
    ANTENNAPARTIALMETALSIDEAREA 45 LAYER met4  ;
    PORT
      LAYER met4 ;
        RECT 113.930000 0.000000 114.230000 0.800000 ;
    END
  END wbs_dat_o[11]
  PIN wbs_dat_o[10]
    DIRECTION OUTPUT ;
    USE SIGNAL ;
    ANTENNADIFFAREA 0.43675 LAYER met4  ;
    ANTENNAPARTIALMETALAREA 7.1574 LAYER met4  ;
    ANTENNAPARTIALMETALSIDEAREA 38.168 LAYER met4  ;
    PORT
      LAYER met4 ;
        RECT 103.580000 0.000000 103.880000 0.800000 ;
    END
  END wbs_dat_o[10]
  PIN wbs_dat_o[9]
    DIRECTION OUTPUT ;
    USE SIGNAL ;
    ANTENNADIFFAREA 0.43675 LAYER met4  ;
    ANTENNAPARTIALMETALAREA 8.4384 LAYER met4  ;
    ANTENNAPARTIALMETALSIDEAREA 45 LAYER met4  ;
    PORT
      LAYER met4 ;
        RECT 93.230000 0.000000 93.530000 0.800000 ;
    END
  END wbs_dat_o[9]
  PIN wbs_dat_o[8]
    DIRECTION OUTPUT ;
    USE SIGNAL ;
    ANTENNADIFFAREA 0.43675 LAYER met4  ;
    ANTENNAPARTIALMETALAREA 0.2034 LAYER met4  ;
    ANTENNAPARTIALMETALSIDEAREA 1.08 LAYER met4  ;
    PORT
      LAYER met4 ;
        RECT 83.570000 0.000000 83.870000 0.800000 ;
    END
  END wbs_dat_o[8]
  PIN wbs_dat_o[7]
    DIRECTION OUTPUT ;
    USE SIGNAL ;
    ANTENNADIFFAREA 0.43675 LAYER met4  ;
    ANTENNAPARTIALMETALAREA 7.3404 LAYER met4  ;
    ANTENNAPARTIALMETALSIDEAREA 39.144 LAYER met4  ;
    PORT
      LAYER met4 ;
        RECT 73.220000 0.000000 73.520000 0.800000 ;
    END
  END wbs_dat_o[7]
  PIN wbs_dat_o[6]
    DIRECTION OUTPUT ;
    USE SIGNAL ;
    ANTENNADIFFAREA 0.43675 LAYER met4  ;
    ANTENNAPARTIALMETALAREA 8.4384 LAYER met4  ;
    ANTENNAPARTIALMETALSIDEAREA 45 LAYER met4  ;
    PORT
      LAYER met4 ;
        RECT 62.870000 0.000000 63.170000 0.800000 ;
    END
  END wbs_dat_o[6]
  PIN wbs_dat_o[5]
    DIRECTION OUTPUT ;
    USE SIGNAL ;
    ANTENNADIFFAREA 0.43675 LAYER met4  ;
    ANTENNAPARTIALMETALAREA 8.4384 LAYER met4  ;
    ANTENNAPARTIALMETALSIDEAREA 45 LAYER met4  ;
    PORT
      LAYER met4 ;
        RECT 52.520000 0.000000 52.820000 0.800000 ;
    END
  END wbs_dat_o[5]
  PIN wbs_dat_o[4]
    DIRECTION OUTPUT ;
    USE SIGNAL ;
    ANTENNADIFFAREA 0.43675 LAYER met4  ;
    ANTENNAPARTIALMETALAREA 8.0724 LAYER met4  ;
    ANTENNAPARTIALMETALSIDEAREA 43.048 LAYER met4  ;
    PORT
      LAYER met4 ;
        RECT 42.170000 0.000000 42.470000 0.800000 ;
    END
  END wbs_dat_o[4]
  PIN wbs_dat_o[3]
    DIRECTION OUTPUT ;
    USE SIGNAL ;
    ANTENNADIFFAREA 0.43675 LAYER met4  ;
    ANTENNAPARTIALMETALAREA 7.7064 LAYER met4  ;
    ANTENNAPARTIALMETALSIDEAREA 41.096 LAYER met4  ;
    PORT
      LAYER met4 ;
        RECT 31.820000 0.000000 32.120000 0.800000 ;
    END
  END wbs_dat_o[3]
  PIN wbs_dat_o[2]
    DIRECTION OUTPUT ;
    USE SIGNAL ;
    ANTENNADIFFAREA 0.43675 LAYER met4  ;
    ANTENNAPARTIALMETALAREA 9.3534 LAYER met4  ;
    ANTENNAPARTIALMETALSIDEAREA 49.88 LAYER met4  ;
    PORT
      LAYER met4 ;
        RECT 21.470000 0.000000 21.770000 0.800000 ;
    END
  END wbs_dat_o[2]
  PIN wbs_dat_o[1]
    DIRECTION OUTPUT ;
    USE SIGNAL ;
    ANTENNADIFFAREA 0.43675 LAYER met4  ;
    ANTENNAPARTIALMETALAREA 9.3534 LAYER met4  ;
    ANTENNAPARTIALMETALSIDEAREA 49.88 LAYER met4  ;
    PORT
      LAYER met4 ;
        RECT 11.120000 0.000000 11.420000 0.800000 ;
    END
  END wbs_dat_o[1]
  PIN wbs_dat_o[0]
    DIRECTION OUTPUT ;
    USE SIGNAL ;
    ANTENNADIFFAREA 0.43675 LAYER met4  ;
    ANTENNAPARTIALMETALAREA 10.8174 LAYER met4  ;
    ANTENNAPARTIALMETALSIDEAREA 57.688 LAYER met4  ;
    PORT
      LAYER met4 ;
        RECT 1.460000 0.000000 1.760000 0.800000 ;
    END
  END wbs_dat_o[0]
  PIN VSS
    DIRECTION INOUT ;
    USE GROUND ;

# P/G power stripe data as pin
    PORT
      LAYER met4 ;
        RECT 27.200000 28.560000 30.560000 1046.080000 ;
        RECT 32.800000 532.800000 34.600000 944.700000 ;
        RECT 525.180000 532.800000 526.980000 944.700000 ;
        RECT 625.600000 28.560000 628.960000 1046.080000 ;
        RECT 598.400000 28.560000 601.760000 1046.080000 ;
        RECT 571.200000 28.560000 574.560000 1046.080000 ;
        RECT 544.000000 28.560000 547.360000 1046.080000 ;
        RECT 788.800000 442.900000 792.160000 1046.080000 ;
        RECT 761.600000 442.900000 764.960000 1046.080000 ;
        RECT 734.400000 442.900000 737.760000 1046.080000 ;
        RECT 707.200000 442.900000 710.560000 1046.080000 ;
        RECT 680.000000 442.900000 683.360000 1046.080000 ;
        RECT 652.800000 442.900000 656.160000 1046.080000 ;
        RECT 1033.600000 442.900000 1036.960000 1046.080000 ;
        RECT 1006.400000 442.900000 1009.760000 1046.080000 ;
        RECT 979.200000 442.900000 982.560000 1046.080000 ;
        RECT 952.000000 442.900000 955.360000 1046.080000 ;
        RECT 924.800000 442.900000 928.160000 1046.080000 ;
        RECT 897.600000 442.900000 900.960000 1046.080000 ;
        RECT 870.400000 442.900000 873.760000 1046.080000 ;
        RECT 843.200000 442.900000 846.560000 1046.080000 ;
        RECT 816.000000 442.900000 819.360000 1046.080000 ;
        RECT 525.180000 32.800000 526.980000 444.700000 ;
        RECT 32.800000 32.800000 34.600000 444.700000 ;
        RECT 54.400000 28.560000 57.760000 34.600000 ;
        RECT 81.600000 28.560000 84.960000 34.600000 ;
        RECT 108.800000 28.560000 112.160000 34.600000 ;
        RECT 136.000000 28.560000 139.360000 34.600000 ;
        RECT 163.200000 28.560000 166.560000 34.600000 ;
        RECT 190.400000 28.560000 193.760000 34.600000 ;
        RECT 217.600000 28.560000 220.960000 34.600000 ;
        RECT 244.800000 28.560000 248.160000 34.600000 ;
        RECT 272.000000 28.560000 275.360000 34.600000 ;
        RECT 299.200000 28.560000 302.560000 34.600000 ;
        RECT 326.400000 28.560000 329.760000 34.600000 ;
        RECT 380.800000 28.560000 384.160000 34.600000 ;
        RECT 353.600000 28.560000 356.960000 34.600000 ;
        RECT 462.400000 28.560000 465.760000 34.600000 ;
        RECT 435.200000 28.560000 438.560000 34.600000 ;
        RECT 408.000000 28.560000 411.360000 34.600000 ;
        RECT 516.800000 28.560000 520.160000 34.600000 ;
        RECT 489.600000 28.560000 492.960000 34.600000 ;
        RECT 108.800000 442.900000 112.160000 534.600000 ;
        RECT 81.600000 442.900000 84.960000 534.600000 ;
        RECT 54.400000 442.900000 57.760000 534.600000 ;
        RECT 244.800000 442.900000 248.160000 534.600000 ;
        RECT 217.600000 442.900000 220.960000 534.600000 ;
        RECT 190.400000 442.900000 193.760000 534.600000 ;
        RECT 163.200000 442.900000 166.560000 534.600000 ;
        RECT 136.000000 442.900000 139.360000 534.600000 ;
        RECT 353.600000 442.900000 356.960000 534.600000 ;
        RECT 326.400000 442.900000 329.760000 534.600000 ;
        RECT 299.200000 442.900000 302.560000 534.600000 ;
        RECT 272.000000 442.900000 275.360000 534.600000 ;
        RECT 380.800000 442.900000 384.160000 534.600000 ;
        RECT 408.000000 442.900000 411.360000 534.600000 ;
        RECT 435.200000 442.900000 438.560000 534.600000 ;
        RECT 462.400000 442.900000 465.760000 534.600000 ;
        RECT 489.600000 442.900000 492.960000 534.600000 ;
        RECT 516.800000 442.900000 520.160000 534.600000 ;
        RECT 632.800000 32.800000 634.600000 444.700000 ;
        RECT 652.800000 28.560000 656.160000 34.600000 ;
        RECT 734.400000 28.560000 737.760000 34.600000 ;
        RECT 707.200000 28.560000 710.560000 34.600000 ;
        RECT 680.000000 28.560000 683.360000 34.600000 ;
        RECT 788.800000 28.560000 792.160000 34.600000 ;
        RECT 761.600000 28.560000 764.960000 34.600000 ;
        RECT 870.400000 28.560000 873.760000 34.600000 ;
        RECT 843.200000 28.560000 846.560000 34.600000 ;
        RECT 816.000000 28.560000 819.360000 34.600000 ;
        RECT 924.800000 28.560000 928.160000 34.600000 ;
        RECT 897.600000 28.560000 900.960000 34.600000 ;
        RECT 1006.400000 28.560000 1009.760000 34.600000 ;
        RECT 979.200000 28.560000 982.560000 34.600000 ;
        RECT 952.000000 28.560000 955.360000 34.600000 ;
        RECT 1033.600000 28.560000 1036.960000 34.600000 ;
        RECT 54.400000 942.900000 57.760000 1046.080000 ;
        RECT 81.600000 942.900000 84.960000 1046.080000 ;
        RECT 108.800000 942.900000 112.160000 1046.080000 ;
        RECT 136.000000 942.900000 139.360000 1046.080000 ;
        RECT 163.200000 942.900000 166.560000 1046.080000 ;
        RECT 190.400000 942.900000 193.760000 1046.080000 ;
        RECT 217.600000 942.900000 220.960000 1046.080000 ;
        RECT 244.800000 942.900000 248.160000 1046.080000 ;
        RECT 353.600000 942.900000 356.960000 1046.080000 ;
        RECT 326.400000 942.900000 329.760000 1046.080000 ;
        RECT 299.200000 942.900000 302.560000 1046.080000 ;
        RECT 272.000000 942.900000 275.360000 1046.080000 ;
        RECT 380.800000 942.900000 384.160000 1046.080000 ;
        RECT 408.000000 942.900000 411.360000 1046.080000 ;
        RECT 435.200000 942.900000 438.560000 1046.080000 ;
        RECT 462.400000 942.900000 465.760000 1046.080000 ;
        RECT 489.600000 942.900000 492.960000 1046.080000 ;
        RECT 516.800000 942.900000 520.160000 1046.080000 ;
        RECT 28.980000 28.515000 30.560000 28.845000 ;
        RECT 54.400000 28.470000 57.760000 28.800000 ;
        RECT 81.600000 28.470000 84.960000 28.800000 ;
        RECT 108.800000 28.470000 112.160000 28.800000 ;
        RECT 136.000000 28.470000 139.360000 28.800000 ;
        RECT 163.200000 28.470000 166.560000 28.800000 ;
        RECT 190.400000 28.470000 193.760000 28.800000 ;
        RECT 217.600000 28.470000 220.960000 28.800000 ;
        RECT 244.800000 28.470000 248.160000 28.800000 ;
        RECT 272.000000 28.470000 275.360000 28.800000 ;
        RECT 299.200000 28.470000 302.560000 28.800000 ;
        RECT 326.400000 28.470000 329.760000 28.800000 ;
        RECT 353.600000 28.470000 356.960000 28.800000 ;
        RECT 380.800000 28.470000 384.160000 28.800000 ;
        RECT 408.000000 28.470000 411.360000 28.800000 ;
        RECT 435.200000 28.470000 438.560000 28.800000 ;
        RECT 462.400000 28.470000 465.760000 28.800000 ;
        RECT 489.600000 28.470000 492.960000 28.800000 ;
        RECT 516.800000 28.470000 520.160000 28.800000 ;
        RECT 544.000000 28.470000 547.360000 28.800000 ;
        RECT 571.200000 28.470000 574.560000 28.800000 ;
        RECT 598.400000 28.470000 601.760000 28.800000 ;
        RECT 625.600000 28.470000 628.960000 28.800000 ;
        RECT 652.800000 28.470000 656.160000 28.800000 ;
        RECT 680.000000 28.470000 683.360000 28.800000 ;
        RECT 707.200000 28.470000 710.560000 28.800000 ;
        RECT 734.400000 28.470000 737.760000 28.800000 ;
        RECT 761.600000 28.470000 764.960000 28.800000 ;
        RECT 788.800000 28.470000 792.160000 28.800000 ;
        RECT 816.000000 28.470000 819.360000 28.800000 ;
        RECT 843.200000 28.470000 846.560000 28.800000 ;
        RECT 870.400000 28.470000 873.760000 28.800000 ;
        RECT 897.600000 28.470000 900.960000 28.800000 ;
        RECT 924.800000 28.470000 928.160000 28.800000 ;
        RECT 952.000000 28.470000 955.360000 28.800000 ;
        RECT 979.200000 28.470000 982.560000 28.800000 ;
        RECT 1006.400000 28.470000 1009.760000 28.800000 ;
        RECT 1033.600000 28.470000 1036.960000 28.800000 ;
        RECT 41.360000 41.360000 43.100000 44.160000 ;
        RECT 41.360000 95.200000 43.100000 98.560000 ;
        RECT 41.360000 68.000000 43.100000 71.360000 ;
        RECT 41.360000 122.400000 43.100000 125.760000 ;
        RECT 41.360000 149.600000 43.100000 152.960000 ;
        RECT 41.360000 176.800000 43.100000 180.160000 ;
        RECT 41.360000 204.000000 43.100000 207.360000 ;
        RECT 41.360000 231.200000 43.100000 234.560000 ;
        RECT 41.360000 258.400000 43.100000 261.760000 ;
        RECT 516.680000 41.360000 518.420000 44.160000 ;
        RECT 516.680000 95.200000 518.420000 98.560000 ;
        RECT 516.680000 68.000000 518.420000 71.360000 ;
        RECT 516.680000 122.400000 518.420000 125.760000 ;
        RECT 516.680000 149.600000 518.420000 152.960000 ;
        RECT 516.680000 176.800000 518.420000 180.160000 ;
        RECT 516.680000 231.200000 518.420000 234.560000 ;
        RECT 516.680000 204.000000 518.420000 207.360000 ;
        RECT 516.680000 258.400000 518.420000 261.760000 ;
        RECT 41.360000 285.600000 43.100000 288.960000 ;
        RECT 41.360000 312.800000 43.100000 316.160000 ;
        RECT 41.360000 367.200000 43.100000 370.560000 ;
        RECT 41.360000 340.000000 43.100000 343.360000 ;
        RECT 41.360000 394.400000 43.100000 397.760000 ;
        RECT 41.360000 421.600000 43.100000 424.960000 ;
        RECT 516.680000 285.600000 518.420000 288.960000 ;
        RECT 516.680000 312.800000 518.420000 316.160000 ;
        RECT 516.680000 367.200000 518.420000 370.560000 ;
        RECT 516.680000 340.000000 518.420000 343.360000 ;
        RECT 516.680000 394.400000 518.420000 397.760000 ;
        RECT 516.680000 421.600000 518.420000 424.960000 ;
        RECT 641.360000 41.360000 643.100000 44.160000 ;
        RECT 641.360000 68.000000 643.100000 71.360000 ;
        RECT 641.360000 95.200000 643.100000 98.560000 ;
        RECT 641.360000 122.400000 643.100000 125.760000 ;
        RECT 641.360000 149.600000 643.100000 152.960000 ;
        RECT 641.360000 176.800000 643.100000 180.160000 ;
        RECT 641.360000 204.000000 643.100000 207.360000 ;
        RECT 641.360000 231.200000 643.100000 234.560000 ;
        RECT 641.360000 258.400000 643.100000 261.760000 ;
        RECT 641.360000 285.600000 643.100000 288.960000 ;
        RECT 641.360000 312.800000 643.100000 316.160000 ;
        RECT 641.360000 367.200000 643.100000 370.560000 ;
        RECT 641.360000 340.000000 643.100000 343.360000 ;
        RECT 641.360000 394.400000 643.100000 397.760000 ;
        RECT 641.360000 421.600000 643.100000 424.960000 ;
        RECT 41.360000 557.600000 43.100000 560.960000 ;
        RECT 41.360000 584.800000 43.100000 588.160000 ;
        RECT 41.360000 639.200000 43.100000 642.560000 ;
        RECT 41.360000 612.000000 43.100000 615.360000 ;
        RECT 41.360000 666.400000 43.100000 669.760000 ;
        RECT 41.360000 693.600000 43.100000 696.960000 ;
        RECT 41.360000 720.800000 43.100000 724.160000 ;
        RECT 41.360000 748.000000 43.100000 751.360000 ;
        RECT 41.360000 775.200000 43.100000 778.560000 ;
        RECT 41.360000 802.400000 43.100000 805.760000 ;
        RECT 516.680000 557.600000 518.420000 560.960000 ;
        RECT 516.680000 584.800000 518.420000 588.160000 ;
        RECT 516.680000 639.200000 518.420000 642.560000 ;
        RECT 516.680000 612.000000 518.420000 615.360000 ;
        RECT 516.680000 666.400000 518.420000 669.760000 ;
        RECT 516.680000 693.600000 518.420000 696.960000 ;
        RECT 516.680000 720.800000 518.420000 724.160000 ;
        RECT 516.680000 748.000000 518.420000 751.360000 ;
        RECT 516.680000 775.200000 518.420000 778.560000 ;
        RECT 516.680000 802.400000 518.420000 805.760000 ;
        RECT 41.360000 829.600000 43.100000 832.960000 ;
        RECT 41.360000 856.800000 43.100000 860.160000 ;
        RECT 41.360000 884.000000 43.100000 887.360000 ;
        RECT 41.360000 911.200000 43.100000 914.560000 ;
        RECT 516.680000 829.600000 518.420000 832.960000 ;
        RECT 516.680000 856.800000 518.420000 860.160000 ;
        RECT 516.680000 884.000000 518.420000 887.360000 ;
        RECT 516.680000 911.200000 518.420000 914.560000 ;
      LAYER met5 ;
        RECT 28.980000 40.800000 643.100000 44.160000 ;
        RECT 28.980000 68.000000 643.100000 71.360000 ;
        RECT 28.980000 95.200000 643.100000 98.560000 ;
        RECT 28.980000 122.400000 643.100000 125.760000 ;
        RECT 28.980000 149.600000 643.100000 152.960000 ;
        RECT 28.980000 176.800000 643.100000 180.160000 ;
        RECT 28.980000 204.000000 643.100000 207.360000 ;
        RECT 28.980000 231.200000 643.100000 234.560000 ;
        RECT 28.980000 258.400000 643.100000 261.760000 ;
        RECT 28.980000 312.800000 643.100000 316.160000 ;
        RECT 28.980000 285.600000 643.100000 288.960000 ;
        RECT 28.980000 394.400000 643.100000 397.760000 ;
        RECT 28.980000 367.200000 643.100000 370.560000 ;
        RECT 28.980000 340.000000 643.100000 343.360000 ;
        RECT 28.980000 421.600000 643.100000 424.960000 ;
        RECT 28.980000 448.800000 1036.960000 452.160000 ;
        RECT 28.980000 503.200000 1036.960000 506.560000 ;
        RECT 28.980000 476.000000 1036.960000 479.360000 ;
        RECT 28.980000 530.400000 1036.960000 533.760000 ;
        RECT 32.800000 32.800000 526.980000 34.600000 ;
        RECT 32.800000 532.800000 526.980000 534.600000 ;
        RECT 32.800000 442.900000 526.980000 444.700000 ;
        RECT 632.800000 32.800000 1036.960000 34.600000 ;
        RECT 632.800000 442.900000 1036.960000 444.700000 ;
        RECT 28.980000 557.600000 1036.960000 560.960000 ;
        RECT 28.980000 584.800000 1036.960000 588.160000 ;
        RECT 28.980000 639.200000 1036.960000 642.560000 ;
        RECT 28.980000 612.000000 1036.960000 615.360000 ;
        RECT 28.980000 666.400000 1036.960000 669.760000 ;
        RECT 28.980000 720.800000 1036.960000 724.160000 ;
        RECT 28.980000 693.600000 1036.960000 696.960000 ;
        RECT 28.980000 802.400000 1036.960000 805.760000 ;
        RECT 28.980000 775.200000 1036.960000 778.560000 ;
        RECT 28.980000 748.000000 1036.960000 751.360000 ;
        RECT 28.980000 829.600000 1036.960000 832.960000 ;
        RECT 28.980000 856.800000 1036.960000 860.160000 ;
        RECT 28.980000 884.000000 1036.960000 887.360000 ;
        RECT 28.980000 911.200000 1036.960000 914.560000 ;
        RECT 28.980000 965.600000 1036.960000 968.960000 ;
        RECT 28.980000 992.800000 1036.960000 996.160000 ;
        RECT 28.980000 1020.000000 1036.960000 1023.360000 ;
        RECT 32.800000 942.900000 526.980000 944.700000 ;
        RECT 544.000000 938.400000 1036.960000 941.760000 ;
        RECT 54.400000 530.400000 57.760000 534.600000 ;
        RECT 81.600000 530.400000 84.960000 534.600000 ;
        RECT 108.800000 530.400000 112.160000 534.600000 ;
        RECT 163.200000 530.400000 166.560000 534.600000 ;
        RECT 136.000000 530.400000 139.360000 534.600000 ;
        RECT 190.400000 530.400000 193.760000 534.600000 ;
        RECT 217.600000 530.400000 220.960000 534.600000 ;
        RECT 244.800000 530.400000 248.160000 534.600000 ;
        RECT 299.200000 530.400000 302.560000 534.600000 ;
        RECT 272.000000 530.400000 275.360000 534.600000 ;
        RECT 326.400000 530.400000 329.760000 534.600000 ;
        RECT 353.600000 530.400000 356.960000 534.600000 ;
        RECT 380.800000 530.400000 384.160000 534.600000 ;
        RECT 435.200000 530.400000 438.560000 534.600000 ;
        RECT 408.000000 530.400000 411.360000 534.600000 ;
        RECT 462.400000 530.400000 465.760000 534.600000 ;
        RECT 489.600000 530.400000 492.960000 534.600000 ;
        RECT 516.800000 530.400000 520.160000 534.600000 ;
    END
# end of P/G power stripe data as pin

  END VSS
  PIN VDD
    DIRECTION INOUT ;
    USE POWER ;

# P/G power stripe data as pin
    PORT
      LAYER met4 ;
        RECT 521.580000 536.400000 523.380000 941.100000 ;
        RECT 36.400000 536.400000 38.200000 941.100000 ;
        RECT 530.400000 28.560000 533.760000 1048.560000 ;
        RECT 612.000000 28.560000 615.360000 1048.560000 ;
        RECT 584.800000 28.560000 588.160000 1048.560000 ;
        RECT 557.600000 28.560000 560.960000 1048.560000 ;
        RECT 802.400000 439.300000 805.760000 1048.560000 ;
        RECT 775.200000 439.300000 778.560000 1048.560000 ;
        RECT 748.000000 439.300000 751.360000 1048.560000 ;
        RECT 720.800000 439.300000 724.160000 1048.560000 ;
        RECT 693.600000 439.300000 696.960000 1048.560000 ;
        RECT 666.400000 439.300000 669.760000 1048.560000 ;
        RECT 639.200000 439.300000 642.560000 1048.560000 ;
        RECT 1047.200000 439.300000 1050.560000 1048.560000 ;
        RECT 1020.000000 439.300000 1023.360000 1048.560000 ;
        RECT 992.800000 439.300000 996.160000 1048.560000 ;
        RECT 965.600000 439.300000 968.960000 1048.560000 ;
        RECT 938.400000 439.300000 941.760000 1048.560000 ;
        RECT 829.600000 439.300000 832.960000 1048.560000 ;
        RECT 856.800000 439.300000 860.160000 1048.560000 ;
        RECT 884.000000 439.300000 887.360000 1048.560000 ;
        RECT 911.200000 439.300000 914.560000 1048.560000 ;
        RECT 521.580000 36.400000 523.380000 441.100000 ;
        RECT 36.400000 36.400000 38.200000 441.100000 ;
        RECT 40.800000 28.560000 44.160000 38.200000 ;
        RECT 122.400000 28.560000 125.760000 38.200000 ;
        RECT 95.200000 28.560000 98.560000 38.200000 ;
        RECT 68.000000 28.560000 71.360000 38.200000 ;
        RECT 176.800000 28.560000 180.160000 38.200000 ;
        RECT 149.600000 28.560000 152.960000 38.200000 ;
        RECT 258.400000 28.560000 261.760000 38.200000 ;
        RECT 231.200000 28.560000 234.560000 38.200000 ;
        RECT 204.000000 28.560000 207.360000 38.200000 ;
        RECT 312.800000 28.560000 316.160000 38.200000 ;
        RECT 285.600000 28.560000 288.960000 38.200000 ;
        RECT 394.400000 28.560000 397.760000 38.200000 ;
        RECT 367.200000 28.560000 370.560000 38.200000 ;
        RECT 340.000000 28.560000 343.360000 38.200000 ;
        RECT 448.800000 28.560000 452.160000 38.200000 ;
        RECT 421.600000 28.560000 424.960000 38.200000 ;
        RECT 503.200000 28.560000 506.560000 38.200000 ;
        RECT 476.000000 28.560000 479.360000 38.200000 ;
        RECT 122.400000 439.300000 125.760000 538.200000 ;
        RECT 95.200000 439.300000 98.560000 538.200000 ;
        RECT 68.000000 439.300000 71.360000 538.200000 ;
        RECT 40.800000 439.300000 44.160000 538.200000 ;
        RECT 258.400000 439.300000 261.760000 538.200000 ;
        RECT 231.200000 439.300000 234.560000 538.200000 ;
        RECT 204.000000 439.300000 207.360000 538.200000 ;
        RECT 176.800000 439.300000 180.160000 538.200000 ;
        RECT 149.600000 439.300000 152.960000 538.200000 ;
        RECT 394.400000 439.300000 397.760000 538.200000 ;
        RECT 367.200000 439.300000 370.560000 538.200000 ;
        RECT 340.000000 439.300000 343.360000 538.200000 ;
        RECT 312.800000 439.300000 316.160000 538.200000 ;
        RECT 285.600000 439.300000 288.960000 538.200000 ;
        RECT 503.200000 439.300000 506.560000 538.200000 ;
        RECT 476.000000 439.300000 479.360000 538.200000 ;
        RECT 448.800000 439.300000 452.160000 538.200000 ;
        RECT 421.600000 439.300000 424.960000 538.200000 ;
        RECT 636.400000 36.400000 638.200000 441.100000 ;
        RECT 666.400000 28.560000 669.760000 38.200000 ;
        RECT 639.200000 28.560000 642.560000 38.200000 ;
        RECT 720.800000 28.560000 724.160000 38.200000 ;
        RECT 693.600000 28.560000 696.960000 38.200000 ;
        RECT 802.400000 28.560000 805.760000 38.200000 ;
        RECT 775.200000 28.560000 778.560000 38.200000 ;
        RECT 748.000000 28.560000 751.360000 38.200000 ;
        RECT 856.800000 28.560000 860.160000 38.200000 ;
        RECT 829.600000 28.560000 832.960000 38.200000 ;
        RECT 938.400000 28.560000 941.760000 38.200000 ;
        RECT 911.200000 28.560000 914.560000 38.200000 ;
        RECT 884.000000 28.560000 887.360000 38.200000 ;
        RECT 992.800000 28.560000 996.160000 38.200000 ;
        RECT 965.600000 28.560000 968.960000 38.200000 ;
        RECT 1047.200000 28.560000 1050.560000 38.200000 ;
        RECT 1020.000000 28.560000 1023.360000 38.200000 ;
        RECT 258.400000 939.300000 261.760000 1048.560000 ;
        RECT 231.200000 939.300000 234.560000 1048.560000 ;
        RECT 204.000000 939.300000 207.360000 1048.560000 ;
        RECT 176.800000 939.300000 180.160000 1048.560000 ;
        RECT 149.600000 939.300000 152.960000 1048.560000 ;
        RECT 122.400000 939.300000 125.760000 1048.560000 ;
        RECT 95.200000 939.300000 98.560000 1048.560000 ;
        RECT 68.000000 939.300000 71.360000 1048.560000 ;
        RECT 40.800000 939.300000 44.160000 1048.560000 ;
        RECT 285.600000 939.300000 288.960000 1048.560000 ;
        RECT 312.800000 939.300000 316.160000 1048.560000 ;
        RECT 340.000000 939.300000 343.360000 1048.560000 ;
        RECT 367.200000 939.300000 370.560000 1048.560000 ;
        RECT 394.400000 939.300000 397.760000 1048.560000 ;
        RECT 421.600000 939.300000 424.960000 1048.560000 ;
        RECT 448.800000 939.300000 452.160000 1048.560000 ;
        RECT 476.000000 939.300000 479.360000 1048.560000 ;
        RECT 503.200000 939.300000 506.560000 1048.560000 ;
        RECT 40.800000 1048.320000 44.160000 1048.650000 ;
        RECT 122.400000 1048.320000 125.760000 1048.650000 ;
        RECT 95.200000 1048.320000 98.560000 1048.650000 ;
        RECT 68.000000 1048.320000 71.360000 1048.650000 ;
        RECT 176.800000 1048.320000 180.160000 1048.650000 ;
        RECT 149.600000 1048.320000 152.960000 1048.650000 ;
        RECT 258.400000 1048.320000 261.760000 1048.650000 ;
        RECT 231.200000 1048.320000 234.560000 1048.650000 ;
        RECT 204.000000 1048.320000 207.360000 1048.650000 ;
        RECT 312.800000 1048.320000 316.160000 1048.650000 ;
        RECT 285.600000 1048.320000 288.960000 1048.650000 ;
        RECT 394.400000 1048.320000 397.760000 1048.650000 ;
        RECT 367.200000 1048.320000 370.560000 1048.650000 ;
        RECT 340.000000 1048.320000 343.360000 1048.650000 ;
        RECT 448.800000 1048.320000 452.160000 1048.650000 ;
        RECT 421.600000 1048.320000 424.960000 1048.650000 ;
        RECT 530.400000 1048.320000 533.760000 1048.650000 ;
        RECT 503.200000 1048.320000 506.560000 1048.650000 ;
        RECT 476.000000 1048.320000 479.360000 1048.650000 ;
        RECT 584.800000 1048.320000 588.160000 1048.650000 ;
        RECT 557.600000 1048.320000 560.960000 1048.650000 ;
        RECT 666.400000 1048.320000 669.760000 1048.650000 ;
        RECT 639.200000 1048.320000 642.560000 1048.650000 ;
        RECT 612.000000 1048.320000 615.360000 1048.650000 ;
        RECT 720.800000 1048.320000 724.160000 1048.650000 ;
        RECT 693.600000 1048.320000 696.960000 1048.650000 ;
        RECT 802.400000 1048.320000 805.760000 1048.650000 ;
        RECT 775.200000 1048.320000 778.560000 1048.650000 ;
        RECT 748.000000 1048.320000 751.360000 1048.650000 ;
        RECT 856.800000 1048.320000 860.160000 1048.650000 ;
        RECT 829.600000 1048.320000 832.960000 1048.650000 ;
        RECT 938.400000 1048.320000 941.760000 1048.650000 ;
        RECT 911.200000 1048.320000 914.560000 1048.650000 ;
        RECT 884.000000 1048.320000 887.360000 1048.650000 ;
        RECT 992.800000 1048.320000 996.160000 1048.650000 ;
        RECT 965.600000 1048.320000 968.960000 1048.650000 ;
        RECT 1020.000000 1048.320000 1023.360000 1048.650000 ;
        RECT 1047.200000 1048.320000 1050.560000 1048.650000 ;
        RECT 44.760000 54.400000 46.500000 57.760000 ;
        RECT 44.760000 81.600000 46.500000 84.960000 ;
        RECT 44.760000 108.800000 46.500000 112.160000 ;
        RECT 44.760000 163.200000 46.500000 166.560000 ;
        RECT 44.760000 136.000000 46.500000 139.360000 ;
        RECT 44.760000 190.400000 46.500000 193.760000 ;
        RECT 44.760000 217.600000 46.500000 220.960000 ;
        RECT 44.760000 244.800000 46.500000 248.160000 ;
        RECT 513.280000 54.400000 515.020000 57.760000 ;
        RECT 513.280000 81.600000 515.020000 84.960000 ;
        RECT 513.280000 108.800000 515.020000 112.160000 ;
        RECT 513.280000 163.200000 515.020000 166.560000 ;
        RECT 513.280000 136.000000 515.020000 139.360000 ;
        RECT 513.280000 190.400000 515.020000 193.760000 ;
        RECT 513.280000 217.600000 515.020000 220.960000 ;
        RECT 513.280000 244.800000 515.020000 248.160000 ;
        RECT 44.760000 299.200000 46.500000 302.560000 ;
        RECT 44.760000 272.000000 46.500000 275.360000 ;
        RECT 44.760000 326.400000 46.500000 329.760000 ;
        RECT 44.760000 353.600000 46.500000 356.960000 ;
        RECT 44.760000 380.800000 46.500000 384.160000 ;
        RECT 44.760000 408.000000 46.500000 411.360000 ;
        RECT 513.280000 299.200000 515.020000 302.560000 ;
        RECT 513.280000 272.000000 515.020000 275.360000 ;
        RECT 513.280000 326.400000 515.020000 329.760000 ;
        RECT 513.280000 353.600000 515.020000 356.960000 ;
        RECT 513.280000 380.800000 515.020000 384.160000 ;
        RECT 513.280000 408.000000 515.020000 411.360000 ;
        RECT 644.760000 54.400000 646.500000 57.760000 ;
        RECT 644.760000 81.600000 646.500000 84.960000 ;
        RECT 644.760000 108.800000 646.500000 112.160000 ;
        RECT 644.760000 163.200000 646.500000 166.560000 ;
        RECT 644.760000 136.000000 646.500000 139.360000 ;
        RECT 644.760000 190.400000 646.500000 193.760000 ;
        RECT 644.760000 217.600000 646.500000 220.960000 ;
        RECT 644.760000 244.800000 646.500000 248.160000 ;
        RECT 644.760000 299.200000 646.500000 302.560000 ;
        RECT 644.760000 272.000000 646.500000 275.360000 ;
        RECT 644.760000 326.400000 646.500000 329.760000 ;
        RECT 644.760000 353.600000 646.500000 356.960000 ;
        RECT 644.760000 380.800000 646.500000 384.160000 ;
        RECT 644.760000 408.000000 646.500000 411.360000 ;
        RECT 44.760000 571.200000 46.500000 574.560000 ;
        RECT 44.760000 544.760000 46.500000 547.360000 ;
        RECT 44.760000 598.400000 46.500000 601.760000 ;
        RECT 44.760000 625.600000 46.500000 628.960000 ;
        RECT 44.760000 652.800000 46.500000 656.160000 ;
        RECT 44.760000 707.200000 46.500000 710.560000 ;
        RECT 44.760000 680.000000 46.500000 683.360000 ;
        RECT 44.760000 734.400000 46.500000 737.760000 ;
        RECT 44.760000 761.600000 46.500000 764.960000 ;
        RECT 44.760000 788.800000 46.500000 792.160000 ;
        RECT 513.280000 571.200000 515.020000 574.560000 ;
        RECT 513.280000 544.760000 515.020000 547.360000 ;
        RECT 513.280000 598.400000 515.020000 601.760000 ;
        RECT 513.280000 625.600000 515.020000 628.960000 ;
        RECT 513.280000 652.800000 515.020000 656.160000 ;
        RECT 513.280000 707.200000 515.020000 710.560000 ;
        RECT 513.280000 680.000000 515.020000 683.360000 ;
        RECT 513.280000 734.400000 515.020000 737.760000 ;
        RECT 513.280000 761.600000 515.020000 764.960000 ;
        RECT 513.280000 788.800000 515.020000 792.160000 ;
        RECT 44.760000 816.000000 46.500000 819.360000 ;
        RECT 44.760000 870.400000 46.500000 873.760000 ;
        RECT 44.760000 843.200000 46.500000 846.560000 ;
        RECT 44.760000 897.600000 46.500000 900.960000 ;
        RECT 44.760000 924.800000 46.500000 928.160000 ;
        RECT 513.280000 816.000000 515.020000 819.360000 ;
        RECT 513.280000 870.400000 515.020000 873.760000 ;
        RECT 513.280000 843.200000 515.020000 846.560000 ;
        RECT 513.280000 897.600000 515.020000 900.960000 ;
        RECT 513.280000 924.800000 515.020000 928.160000 ;
      LAYER met5 ;
        RECT 36.400000 54.400000 646.500000 57.760000 ;
        RECT 40.800000 27.200000 1050.560000 30.560000 ;
        RECT 36.400000 81.600000 646.500000 84.960000 ;
        RECT 36.400000 108.800000 646.500000 112.160000 ;
        RECT 36.400000 136.000000 646.500000 139.360000 ;
        RECT 36.400000 163.200000 646.500000 166.560000 ;
        RECT 36.400000 190.400000 646.500000 193.760000 ;
        RECT 36.400000 217.600000 646.500000 220.960000 ;
        RECT 36.400000 244.800000 646.500000 248.160000 ;
        RECT 36.400000 326.400000 646.500000 329.760000 ;
        RECT 36.400000 299.200000 646.500000 302.560000 ;
        RECT 36.400000 272.000000 646.500000 275.360000 ;
        RECT 36.400000 380.800000 646.500000 384.160000 ;
        RECT 36.400000 353.600000 646.500000 356.960000 ;
        RECT 530.400000 435.200000 615.360000 438.560000 ;
        RECT 36.400000 408.000000 646.500000 411.360000 ;
        RECT 40.800000 462.400000 1050.560000 465.760000 ;
        RECT 40.800000 489.600000 1050.560000 492.960000 ;
        RECT 40.800000 516.800000 1050.560000 520.160000 ;
        RECT 36.400000 36.400000 523.380000 38.200000 ;
        RECT 36.400000 536.400000 523.380000 538.200000 ;
        RECT 36.400000 439.300000 523.380000 441.100000 ;
        RECT 636.400000 36.400000 1050.560000 38.200000 ;
        RECT 636.400000 439.300000 1050.560000 441.100000 ;
        RECT 36.400000 571.200000 1050.560000 574.560000 ;
        RECT 36.400000 544.000000 1050.560000 547.360000 ;
        RECT 36.400000 598.400000 1050.560000 601.760000 ;
        RECT 36.400000 625.600000 1050.560000 628.960000 ;
        RECT 36.400000 652.800000 1050.560000 656.160000 ;
        RECT 36.400000 734.400000 1050.560000 737.760000 ;
        RECT 36.400000 707.200000 1050.560000 710.560000 ;
        RECT 36.400000 680.000000 1050.560000 683.360000 ;
        RECT 36.400000 788.800000 1050.560000 792.160000 ;
        RECT 36.400000 761.600000 1050.560000 764.960000 ;
        RECT 36.400000 816.000000 1050.560000 819.360000 ;
        RECT 36.400000 843.200000 1050.560000 846.560000 ;
        RECT 36.400000 870.400000 1050.560000 873.760000 ;
        RECT 36.400000 924.800000 1050.560000 928.160000 ;
        RECT 36.400000 897.600000 1050.560000 900.960000 ;
        RECT 40.800000 952.000000 1050.560000 955.360000 ;
        RECT 40.800000 1006.400000 1050.560000 1009.760000 ;
        RECT 40.800000 979.200000 1050.560000 982.560000 ;
        RECT 40.800000 1033.600000 1050.560000 1036.960000 ;
        RECT 36.400000 939.300000 523.380000 941.100000 ;
    END
# end of P/G power stripe data as pin

  END VDD
  OBS
    LAYER li1 ;
      RECT 0.000000 0.000000 1080.080000 1077.120000 ;
    LAYER met1 ;
      RECT 0.000000 0.000000 1080.080000 1077.120000 ;
    LAYER met2 ;
      RECT 0.000000 0.000000 1080.080000 1077.120000 ;
    LAYER met3 ;
      RECT 0.000000 0.000000 1080.080000 1077.120000 ;
    LAYER met4 ;
      RECT 0.000000 0.000000 1080.080000 1077.120000 ;
    LAYER met5 ;
      RECT 0.000000 0.000000 1080.080000 1077.120000 ;
  END
END top

END LIBRARY
